VERSION 5.8 ;
BUSBITCHARS "[]" ;
DIVIDERCHAR "/" ;
UNITS
    DATABASE MICRONS 1000 ;
END UNITS

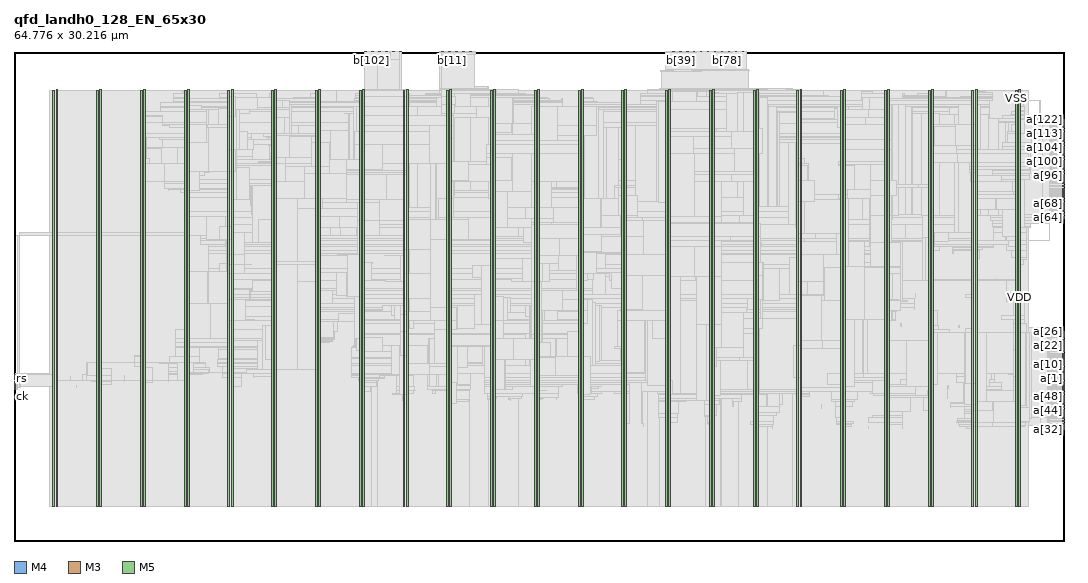
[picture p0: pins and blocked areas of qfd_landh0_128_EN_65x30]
MACRO qfd_landh0_128_EN_65x30
  FOREIGN qfd_landh0_128_EN_65x30 0 0 ;
  CLASS BLOCK ;
  SIZE 64.776 BY 30.216 ;
  PIN a[0]
    DIRECTION INPUT ;
    USE SIGNAL ;
    PORT
      LAYER M4 ;
        RECT  64.692 9.936 64.776 9.96 ;
    END
  END a[0]
  PIN a[100]
    DIRECTION INPUT ;
    USE SIGNAL ;
    PORT
      LAYER M4 ;
        RECT  64.692 23.376 64.776 23.4 ;
    END
  END a[100]
  PIN a[101]
    DIRECTION INPUT ;
    USE SIGNAL ;
    PORT
      LAYER M4 ;
        RECT  64.692 23.472 64.776 23.496 ;
    END
  END a[101]
  PIN a[102]
    DIRECTION INPUT ;
    USE SIGNAL ;
    PORT
      LAYER M4 ;
        RECT  64.692 23.568 64.776 23.592 ;
    END
  END a[102]
  PIN a[103]
    DIRECTION INPUT ;
    USE SIGNAL ;
    PORT
      LAYER M4 ;
        RECT  64.692 23.664 64.776 23.688 ;
    END
  END a[103]
  PIN a[104]
    DIRECTION INPUT ;
    USE SIGNAL ;
    PORT
      LAYER M4 ;
        RECT  64.692 23.76 64.776 23.784 ;
    END
  END a[104]
  PIN a[105]
    DIRECTION INPUT ;
    USE SIGNAL ;
    PORT
      LAYER M4 ;
        RECT  64.692 23.856 64.776 23.88 ;
    END
  END a[105]
  PIN a[106]
    DIRECTION INPUT ;
    USE SIGNAL ;
    PORT
      LAYER M4 ;
        RECT  64.692 23.952 64.776 23.976 ;
    END
  END a[106]
  PIN a[107]
    DIRECTION INPUT ;
    USE SIGNAL ;
    PORT
      LAYER M4 ;
        RECT  64.692 24.048 64.776 24.072 ;
    END
  END a[107]
  PIN a[108]
    DIRECTION INPUT ;
    USE SIGNAL ;
    PORT
      LAYER M4 ;
        RECT  64.692 24.144 64.776 24.168 ;
    END
  END a[108]
  PIN a[109]
    DIRECTION INPUT ;
    USE SIGNAL ;
    PORT
      LAYER M4 ;
        RECT  64.692 24.24 64.776 24.264 ;
    END
  END a[109]
  PIN a[10]
    DIRECTION INPUT ;
    USE SIGNAL ;
    PORT
      LAYER M4 ;
        RECT  64.692 10.896 64.776 10.92 ;
    END
  END a[10]
  PIN a[110]
    DIRECTION INPUT ;
    USE SIGNAL ;
    PORT
      LAYER M4 ;
        RECT  64.692 24.336 64.776 24.36 ;
    END
  END a[110]
  PIN a[111]
    DIRECTION INPUT ;
    USE SIGNAL ;
    PORT
      LAYER M4 ;
        RECT  64.692 24.432 64.776 24.456 ;
    END
  END a[111]
  PIN a[112]
    DIRECTION INPUT ;
    USE SIGNAL ;
    PORT
      LAYER M4 ;
        RECT  64.692 24.528 64.776 24.552 ;
    END
  END a[112]
  PIN a[113]
    DIRECTION INPUT ;
    USE SIGNAL ;
    PORT
      LAYER M4 ;
        RECT  64.692 24.624 64.776 24.648 ;
    END
  END a[113]
  PIN a[114]
    DIRECTION INPUT ;
    USE SIGNAL ;
    PORT
      LAYER M4 ;
        RECT  64.692 24.72 64.776 24.744 ;
    END
  END a[114]
  PIN a[115]
    DIRECTION INPUT ;
    USE SIGNAL ;
    PORT
      LAYER M4 ;
        RECT  64.692 24.816 64.776 24.84 ;
    END
  END a[115]
  PIN a[116]
    DIRECTION INPUT ;
    USE SIGNAL ;
    PORT
      LAYER M4 ;
        RECT  64.692 24.912 64.776 24.936 ;
    END
  END a[116]
  PIN a[117]
    DIRECTION INPUT ;
    USE SIGNAL ;
    PORT
      LAYER M4 ;
        RECT  64.692 25.008 64.776 25.032 ;
    END
  END a[117]
  PIN a[118]
    DIRECTION INPUT ;
    USE SIGNAL ;
    PORT
      LAYER M4 ;
        RECT  64.692 25.104 64.776 25.128 ;
    END
  END a[118]
  PIN a[119]
    DIRECTION INPUT ;
    USE SIGNAL ;
    PORT
      LAYER M4 ;
        RECT  64.692 25.2 64.776 25.224 ;
    END
  END a[119]
  PIN a[11]
    DIRECTION INPUT ;
    USE SIGNAL ;
    PORT
      LAYER M4 ;
        RECT  64.692 10.992 64.776 11.016 ;
    END
  END a[11]
  PIN a[120]
    DIRECTION INPUT ;
    USE SIGNAL ;
    PORT
      LAYER M4 ;
        RECT  64.692 25.296 64.776 25.32 ;
    END
  END a[120]
  PIN a[121]
    DIRECTION INPUT ;
    USE SIGNAL ;
    PORT
      LAYER M4 ;
        RECT  64.692 25.392 64.776 25.416 ;
    END
  END a[121]
  PIN a[122]
    DIRECTION INPUT ;
    USE SIGNAL ;
    PORT
      LAYER M4 ;
        RECT  64.692 25.488 64.776 25.512 ;
    END
  END a[122]
  PIN a[123]
    DIRECTION INPUT ;
    USE SIGNAL ;
    PORT
      LAYER M4 ;
        RECT  64.692 25.584 64.776 25.608 ;
    END
  END a[123]
  PIN a[124]
    DIRECTION INPUT ;
    USE SIGNAL ;
    PORT
      LAYER M4 ;
        RECT  64.692 25.68 64.776 25.704 ;
    END
  END a[124]
  PIN a[125]
    DIRECTION INPUT ;
    USE SIGNAL ;
    PORT
      LAYER M4 ;
        RECT  64.692 25.776 64.776 25.8 ;
    END
  END a[125]
  PIN a[126]
    DIRECTION INPUT ;
    USE SIGNAL ;
    PORT
      LAYER M4 ;
        RECT  64.692 25.872 64.776 25.896 ;
    END
  END a[126]
  PIN a[127]
    DIRECTION INPUT ;
    USE SIGNAL ;
    PORT
      LAYER M4 ;
        RECT  64.692 25.968 64.776 25.992 ;
    END
  END a[127]
  PIN a[12]
    DIRECTION INPUT ;
    USE SIGNAL ;
    PORT
      LAYER M4 ;
        RECT  64.692 11.088 64.776 11.112 ;
    END
  END a[12]
  PIN a[13]
    DIRECTION INPUT ;
    USE SIGNAL ;
    PORT
      LAYER M4 ;
        RECT  64.692 11.184 64.776 11.208 ;
    END
  END a[13]
  PIN a[14]
    DIRECTION INPUT ;
    USE SIGNAL ;
    PORT
      LAYER M4 ;
        RECT  64.692 11.28 64.776 11.304 ;
    END
  END a[14]
  PIN a[15]
    DIRECTION INPUT ;
    USE SIGNAL ;
    PORT
      LAYER M4 ;
        RECT  64.692 11.376 64.776 11.4 ;
    END
  END a[15]
  PIN a[16]
    DIRECTION INPUT ;
    USE SIGNAL ;
    PORT
      LAYER M4 ;
        RECT  64.692 11.472 64.776 11.496 ;
    END
  END a[16]
  PIN a[17]
    DIRECTION INPUT ;
    USE SIGNAL ;
    PORT
      LAYER M4 ;
        RECT  64.692 11.568 64.776 11.592 ;
    END
  END a[17]
  PIN a[18]
    DIRECTION INPUT ;
    USE SIGNAL ;
    PORT
      LAYER M4 ;
        RECT  64.692 11.664 64.776 11.688 ;
    END
  END a[18]
  PIN a[19]
    DIRECTION INPUT ;
    USE SIGNAL ;
    PORT
      LAYER M4 ;
        RECT  64.692 11.76 64.776 11.784 ;
    END
  END a[19]
  PIN a[1]
    DIRECTION INPUT ;
    USE SIGNAL ;
    PORT
      LAYER M4 ;
        RECT  64.692 10.032 64.776 10.056 ;
    END
  END a[1]
  PIN a[20]
    DIRECTION INPUT ;
    USE SIGNAL ;
    PORT
      LAYER M4 ;
        RECT  64.692 11.856 64.776 11.88 ;
    END
  END a[20]
  PIN a[21]
    DIRECTION INPUT ;
    USE SIGNAL ;
    PORT
      LAYER M4 ;
        RECT  64.692 11.952 64.776 11.976 ;
    END
  END a[21]
  PIN a[22]
    DIRECTION INPUT ;
    USE SIGNAL ;
    PORT
      LAYER M4 ;
        RECT  64.692 12.048 64.776 12.072 ;
    END
  END a[22]
  PIN a[23]
    DIRECTION INPUT ;
    USE SIGNAL ;
    PORT
      LAYER M4 ;
        RECT  64.692 12.144 64.776 12.168 ;
    END
  END a[23]
  PIN a[24]
    DIRECTION INPUT ;
    USE SIGNAL ;
    PORT
      LAYER M4 ;
        RECT  64.692 12.24 64.776 12.264 ;
    END
  END a[24]
  PIN a[25]
    DIRECTION INPUT ;
    USE SIGNAL ;
    PORT
      LAYER M4 ;
        RECT  64.692 12.336 64.776 12.36 ;
    END
  END a[25]
  PIN a[26]
    DIRECTION INPUT ;
    USE SIGNAL ;
    PORT
      LAYER M4 ;
        RECT  64.692 12.432 64.776 12.456 ;
    END
  END a[26]
  PIN a[27]
    DIRECTION INPUT ;
    USE SIGNAL ;
    PORT
      LAYER M4 ;
        RECT  64.692 12.528 64.776 12.552 ;
    END
  END a[27]
  PIN a[28]
    DIRECTION INPUT ;
    USE SIGNAL ;
    PORT
      LAYER M4 ;
        RECT  64.692 12.624 64.776 12.648 ;
    END
  END a[28]
  PIN a[29]
    DIRECTION INPUT ;
    USE SIGNAL ;
    PORT
      LAYER M4 ;
        RECT  64.692 12.72 64.776 12.744 ;
    END
  END a[29]
  PIN a[2]
    DIRECTION INPUT ;
    USE SIGNAL ;
    PORT
      LAYER M4 ;
        RECT  64.692 10.128 64.776 10.152 ;
    END
  END a[2]
  PIN a[30]
    DIRECTION INPUT ;
    USE SIGNAL ;
    PORT
      LAYER M4 ;
        RECT  64.692 12.816 64.776 12.84 ;
    END
  END a[30]
  PIN a[31]
    DIRECTION INPUT ;
    USE SIGNAL ;
    PORT
      LAYER M4 ;
        RECT  64.692 12.912 64.776 12.936 ;
    END
  END a[31]
  PIN a[32]
    DIRECTION INPUT ;
    USE SIGNAL ;
    PORT
      LAYER M4 ;
        RECT  64.692 6.864 64.776 6.888 ;
    END
  END a[32]
  PIN a[33]
    DIRECTION INPUT ;
    USE SIGNAL ;
    PORT
      LAYER M4 ;
        RECT  64.692 6.96 64.776 6.984 ;
    END
  END a[33]
  PIN a[34]
    DIRECTION INPUT ;
    USE SIGNAL ;
    PORT
      LAYER M4 ;
        RECT  64.692 7.056 64.776 7.08 ;
    END
  END a[34]
  PIN a[35]
    DIRECTION INPUT ;
    USE SIGNAL ;
    PORT
      LAYER M4 ;
        RECT  64.692 7.152 64.776 7.176 ;
    END
  END a[35]
  PIN a[36]
    DIRECTION INPUT ;
    USE SIGNAL ;
    PORT
      LAYER M4 ;
        RECT  64.692 7.248 64.776 7.272 ;
    END
  END a[36]
  PIN a[37]
    DIRECTION INPUT ;
    USE SIGNAL ;
    PORT
      LAYER M4 ;
        RECT  64.692 7.344 64.776 7.368 ;
    END
  END a[37]
  PIN a[38]
    DIRECTION INPUT ;
    USE SIGNAL ;
    PORT
      LAYER M4 ;
        RECT  64.692 7.44 64.776 7.464 ;
    END
  END a[38]
  PIN a[39]
    DIRECTION INPUT ;
    USE SIGNAL ;
    PORT
      LAYER M4 ;
        RECT  64.692 7.536 64.776 7.56 ;
    END
  END a[39]
  PIN a[3]
    DIRECTION INPUT ;
    USE SIGNAL ;
    PORT
      LAYER M4 ;
        RECT  64.692 10.224 64.776 10.248 ;
    END
  END a[3]
  PIN a[40]
    DIRECTION INPUT ;
    USE SIGNAL ;
    PORT
      LAYER M4 ;
        RECT  64.692 7.632 64.776 7.656 ;
    END
  END a[40]
  PIN a[41]
    DIRECTION INPUT ;
    USE SIGNAL ;
    PORT
      LAYER M4 ;
        RECT  64.692 7.728 64.776 7.752 ;
    END
  END a[41]
  PIN a[42]
    DIRECTION INPUT ;
    USE SIGNAL ;
    PORT
      LAYER M4 ;
        RECT  64.692 7.824 64.776 7.848 ;
    END
  END a[42]
  PIN a[43]
    DIRECTION INPUT ;
    USE SIGNAL ;
    PORT
      LAYER M4 ;
        RECT  64.692 7.92 64.776 7.944 ;
    END
  END a[43]
  PIN a[44]
    DIRECTION INPUT ;
    USE SIGNAL ;
    PORT
      LAYER M4 ;
        RECT  64.692 8.016 64.776 8.04 ;
    END
  END a[44]
  PIN a[45]
    DIRECTION INPUT ;
    USE SIGNAL ;
    PORT
      LAYER M4 ;
        RECT  64.692 8.112 64.776 8.136 ;
    END
  END a[45]
  PIN a[46]
    DIRECTION INPUT ;
    USE SIGNAL ;
    PORT
      LAYER M4 ;
        RECT  64.692 8.208 64.776 8.232 ;
    END
  END a[46]
  PIN a[47]
    DIRECTION INPUT ;
    USE SIGNAL ;
    PORT
      LAYER M4 ;
        RECT  64.692 8.304 64.776 8.328 ;
    END
  END a[47]
  PIN a[48]
    DIRECTION INPUT ;
    USE SIGNAL ;
    PORT
      LAYER M4 ;
        RECT  64.692 8.4 64.776 8.424 ;
    END
  END a[48]
  PIN a[49]
    DIRECTION INPUT ;
    USE SIGNAL ;
    PORT
      LAYER M4 ;
        RECT  64.692 8.496 64.776 8.52 ;
    END
  END a[49]
  PIN a[4]
    DIRECTION INPUT ;
    USE SIGNAL ;
    PORT
      LAYER M4 ;
        RECT  64.692 10.32 64.776 10.344 ;
    END
  END a[4]
  PIN a[50]
    DIRECTION INPUT ;
    USE SIGNAL ;
    PORT
      LAYER M4 ;
        RECT  64.692 8.592 64.776 8.616 ;
    END
  END a[50]
  PIN a[51]
    DIRECTION INPUT ;
    USE SIGNAL ;
    PORT
      LAYER M4 ;
        RECT  64.692 8.688 64.776 8.712 ;
    END
  END a[51]
  PIN a[52]
    DIRECTION INPUT ;
    USE SIGNAL ;
    PORT
      LAYER M4 ;
        RECT  64.692 8.784 64.776 8.808 ;
    END
  END a[52]
  PIN a[53]
    DIRECTION INPUT ;
    USE SIGNAL ;
    PORT
      LAYER M4 ;
        RECT  64.692 8.88 64.776 8.904 ;
    END
  END a[53]
  PIN a[54]
    DIRECTION INPUT ;
    USE SIGNAL ;
    PORT
      LAYER M4 ;
        RECT  64.692 8.976 64.776 9 ;
    END
  END a[54]
  PIN a[55]
    DIRECTION INPUT ;
    USE SIGNAL ;
    PORT
      LAYER M4 ;
        RECT  64.692 9.072 64.776 9.096 ;
    END
  END a[55]
  PIN a[56]
    DIRECTION INPUT ;
    USE SIGNAL ;
    PORT
      LAYER M4 ;
        RECT  64.692 9.168 64.776 9.192 ;
    END
  END a[56]
  PIN a[57]
    DIRECTION INPUT ;
    USE SIGNAL ;
    PORT
      LAYER M4 ;
        RECT  64.692 9.264 64.776 9.288 ;
    END
  END a[57]
  PIN a[58]
    DIRECTION INPUT ;
    USE SIGNAL ;
    PORT
      LAYER M4 ;
        RECT  64.692 9.36 64.776 9.384 ;
    END
  END a[58]
  PIN a[59]
    DIRECTION INPUT ;
    USE SIGNAL ;
    PORT
      LAYER M4 ;
        RECT  64.692 9.456 64.776 9.48 ;
    END
  END a[59]
  PIN a[5]
    DIRECTION INPUT ;
    USE SIGNAL ;
    PORT
      LAYER M4 ;
        RECT  64.692 10.416 64.776 10.44 ;
    END
  END a[5]
  PIN a[60]
    DIRECTION INPUT ;
    USE SIGNAL ;
    PORT
      LAYER M4 ;
        RECT  64.692 9.552 64.776 9.576 ;
    END
  END a[60]
  PIN a[61]
    DIRECTION INPUT ;
    USE SIGNAL ;
    PORT
      LAYER M4 ;
        RECT  64.692 9.648 64.776 9.672 ;
    END
  END a[61]
  PIN a[62]
    DIRECTION INPUT ;
    USE SIGNAL ;
    PORT
      LAYER M4 ;
        RECT  64.692 9.744 64.776 9.768 ;
    END
  END a[62]
  PIN a[63]
    DIRECTION INPUT ;
    USE SIGNAL ;
    PORT
      LAYER M4 ;
        RECT  64.692 9.84 64.776 9.864 ;
    END
  END a[63]
  PIN a[64]
    DIRECTION INPUT ;
    USE SIGNAL ;
    PORT
      LAYER M4 ;
        RECT  64.692 19.92 64.776 19.944 ;
    END
  END a[64]
  PIN a[65]
    DIRECTION INPUT ;
    USE SIGNAL ;
    PORT
      LAYER M4 ;
        RECT  64.692 20.016 64.776 20.04 ;
    END
  END a[65]
  PIN a[66]
    DIRECTION INPUT ;
    USE SIGNAL ;
    PORT
      LAYER M4 ;
        RECT  64.692 20.112 64.776 20.136 ;
    END
  END a[66]
  PIN a[67]
    DIRECTION INPUT ;
    USE SIGNAL ;
    PORT
      LAYER M4 ;
        RECT  64.692 20.208 64.776 20.232 ;
    END
  END a[67]
  PIN a[68]
    DIRECTION INPUT ;
    USE SIGNAL ;
    PORT
      LAYER M4 ;
        RECT  64.692 20.304 64.776 20.328 ;
    END
  END a[68]
  PIN a[69]
    DIRECTION INPUT ;
    USE SIGNAL ;
    PORT
      LAYER M4 ;
        RECT  64.692 20.4 64.776 20.424 ;
    END
  END a[69]
  PIN a[6]
    DIRECTION INPUT ;
    USE SIGNAL ;
    PORT
      LAYER M4 ;
        RECT  64.692 10.512 64.776 10.536 ;
    END
  END a[6]
  PIN a[70]
    DIRECTION INPUT ;
    USE SIGNAL ;
    PORT
      LAYER M4 ;
        RECT  64.692 20.496 64.776 20.52 ;
    END
  END a[70]
  PIN a[71]
    DIRECTION INPUT ;
    USE SIGNAL ;
    PORT
      LAYER M4 ;
        RECT  64.692 20.592 64.776 20.616 ;
    END
  END a[71]
  PIN a[72]
    DIRECTION INPUT ;
    USE SIGNAL ;
    PORT
      LAYER M4 ;
        RECT  64.692 20.688 64.776 20.712 ;
    END
  END a[72]
  PIN a[73]
    DIRECTION INPUT ;
    USE SIGNAL ;
    PORT
      LAYER M4 ;
        RECT  64.692 20.784 64.776 20.808 ;
    END
  END a[73]
  PIN a[74]
    DIRECTION INPUT ;
    USE SIGNAL ;
    PORT
      LAYER M4 ;
        RECT  64.692 20.88 64.776 20.904 ;
    END
  END a[74]
  PIN a[75]
    DIRECTION INPUT ;
    USE SIGNAL ;
    PORT
      LAYER M4 ;
        RECT  64.692 20.976 64.776 21 ;
    END
  END a[75]
  PIN a[76]
    DIRECTION INPUT ;
    USE SIGNAL ;
    PORT
      LAYER M4 ;
        RECT  64.692 21.072 64.776 21.096 ;
    END
  END a[76]
  PIN a[77]
    DIRECTION INPUT ;
    USE SIGNAL ;
    PORT
      LAYER M4 ;
        RECT  64.692 21.168 64.776 21.192 ;
    END
  END a[77]
  PIN a[78]
    DIRECTION INPUT ;
    USE SIGNAL ;
    PORT
      LAYER M4 ;
        RECT  64.692 21.264 64.776 21.288 ;
    END
  END a[78]
  PIN a[79]
    DIRECTION INPUT ;
    USE SIGNAL ;
    PORT
      LAYER M4 ;
        RECT  64.692 21.36 64.776 21.384 ;
    END
  END a[79]
  PIN a[7]
    DIRECTION INPUT ;
    USE SIGNAL ;
    PORT
      LAYER M4 ;
        RECT  64.692 10.608 64.776 10.632 ;
    END
  END a[7]
  PIN a[80]
    DIRECTION INPUT ;
    USE SIGNAL ;
    PORT
      LAYER M4 ;
        RECT  64.692 21.456 64.776 21.48 ;
    END
  END a[80]
  PIN a[81]
    DIRECTION INPUT ;
    USE SIGNAL ;
    PORT
      LAYER M4 ;
        RECT  64.692 21.552 64.776 21.576 ;
    END
  END a[81]
  PIN a[82]
    DIRECTION INPUT ;
    USE SIGNAL ;
    PORT
      LAYER M4 ;
        RECT  64.692 21.648 64.776 21.672 ;
    END
  END a[82]
  PIN a[83]
    DIRECTION INPUT ;
    USE SIGNAL ;
    PORT
      LAYER M4 ;
        RECT  64.692 21.744 64.776 21.768 ;
    END
  END a[83]
  PIN a[84]
    DIRECTION INPUT ;
    USE SIGNAL ;
    PORT
      LAYER M4 ;
        RECT  64.692 21.84 64.776 21.864 ;
    END
  END a[84]
  PIN a[85]
    DIRECTION INPUT ;
    USE SIGNAL ;
    PORT
      LAYER M4 ;
        RECT  64.692 21.936 64.776 21.96 ;
    END
  END a[85]
  PIN a[86]
    DIRECTION INPUT ;
    USE SIGNAL ;
    PORT
      LAYER M4 ;
        RECT  64.692 22.032 64.776 22.056 ;
    END
  END a[86]
  PIN a[87]
    DIRECTION INPUT ;
    USE SIGNAL ;
    PORT
      LAYER M4 ;
        RECT  64.692 22.128 64.776 22.152 ;
    END
  END a[87]
  PIN a[88]
    DIRECTION INPUT ;
    USE SIGNAL ;
    PORT
      LAYER M4 ;
        RECT  64.692 22.224 64.776 22.248 ;
    END
  END a[88]
  PIN a[89]
    DIRECTION INPUT ;
    USE SIGNAL ;
    PORT
      LAYER M4 ;
        RECT  64.692 22.32 64.776 22.344 ;
    END
  END a[89]
  PIN a[8]
    DIRECTION INPUT ;
    USE SIGNAL ;
    PORT
      LAYER M4 ;
        RECT  64.692 10.704 64.776 10.728 ;
    END
  END a[8]
  PIN a[90]
    DIRECTION INPUT ;
    USE SIGNAL ;
    PORT
      LAYER M4 ;
        RECT  64.692 22.416 64.776 22.44 ;
    END
  END a[90]
  PIN a[91]
    DIRECTION INPUT ;
    USE SIGNAL ;
    PORT
      LAYER M4 ;
        RECT  64.692 22.512 64.776 22.536 ;
    END
  END a[91]
  PIN a[92]
    DIRECTION INPUT ;
    USE SIGNAL ;
    PORT
      LAYER M4 ;
        RECT  64.692 22.608 64.776 22.632 ;
    END
  END a[92]
  PIN a[93]
    DIRECTION INPUT ;
    USE SIGNAL ;
    PORT
      LAYER M4 ;
        RECT  64.692 22.704 64.776 22.728 ;
    END
  END a[93]
  PIN a[94]
    DIRECTION INPUT ;
    USE SIGNAL ;
    PORT
      LAYER M4 ;
        RECT  64.692 22.8 64.776 22.824 ;
    END
  END a[94]
  PIN a[95]
    DIRECTION INPUT ;
    USE SIGNAL ;
    PORT
      LAYER M4 ;
        RECT  64.692 22.896 64.776 22.92 ;
    END
  END a[95]
  PIN a[96]
    DIRECTION INPUT ;
    USE SIGNAL ;
    PORT
      LAYER M4 ;
        RECT  64.692 22.992 64.776 23.016 ;
    END
  END a[96]
  PIN a[97]
    DIRECTION INPUT ;
    USE SIGNAL ;
    PORT
      LAYER M4 ;
        RECT  64.692 23.088 64.776 23.112 ;
    END
  END a[97]
  PIN a[98]
    DIRECTION INPUT ;
    USE SIGNAL ;
    PORT
      LAYER M4 ;
        RECT  64.692 23.184 64.776 23.208 ;
    END
  END a[98]
  PIN a[99]
    DIRECTION INPUT ;
    USE SIGNAL ;
    PORT
      LAYER M4 ;
        RECT  64.692 23.28 64.776 23.304 ;
    END
  END a[99]
  PIN a[9]
    DIRECTION INPUT ;
    USE SIGNAL ;
    PORT
      LAYER M4 ;
        RECT  64.692 10.8 64.776 10.824 ;
    END
  END a[9]
  PIN b[0]
    DIRECTION OUTPUT ;
    USE SIGNAL ;
    PORT
      LAYER M3 ;
        RECT  26.244 30.179 26.262 30.216 ;
    END
  END b[0]
  PIN b[100]
    DIRECTION OUTPUT ;
    USE SIGNAL ;
    PORT
      LAYER M3 ;
        RECT  21.924 30.179 21.942 30.216 ;
    END
  END b[100]
  PIN b[101]
    DIRECTION OUTPUT ;
    USE SIGNAL ;
    PORT
      LAYER M3 ;
        RECT  21.996 30.179 22.014 30.216 ;
    END
  END b[101]
  PIN b[102]
    DIRECTION OUTPUT ;
    USE SIGNAL ;
    PORT
      LAYER M3 ;
        RECT  22.068 30.179 22.086 30.216 ;
    END
  END b[102]
  PIN b[103]
    DIRECTION OUTPUT ;
    USE SIGNAL ;
    PORT
      LAYER M3 ;
        RECT  22.14 30.179 22.158 30.216 ;
    END
  END b[103]
  PIN b[104]
    DIRECTION OUTPUT ;
    USE SIGNAL ;
    PORT
      LAYER M3 ;
        RECT  22.212 30.179 22.23 30.216 ;
    END
  END b[104]
  PIN b[105]
    DIRECTION OUTPUT ;
    USE SIGNAL ;
    PORT
      LAYER M3 ;
        RECT  22.284 30.179 22.302 30.216 ;
    END
  END b[105]
  PIN b[106]
    DIRECTION OUTPUT ;
    USE SIGNAL ;
    PORT
      LAYER M3 ;
        RECT  22.356 30.179 22.374 30.216 ;
    END
  END b[106]
  PIN b[107]
    DIRECTION OUTPUT ;
    USE SIGNAL ;
    PORT
      LAYER M3 ;
        RECT  22.428 30.179 22.446 30.216 ;
    END
  END b[107]
  PIN b[108]
    DIRECTION OUTPUT ;
    USE SIGNAL ;
    PORT
      LAYER M3 ;
        RECT  22.5 30.179 22.518 30.216 ;
    END
  END b[108]
  PIN b[109]
    DIRECTION OUTPUT ;
    USE SIGNAL ;
    PORT
      LAYER M3 ;
        RECT  22.572 30.179 22.59 30.216 ;
    END
  END b[109]
  PIN b[10]
    DIRECTION OUTPUT ;
    USE SIGNAL ;
    PORT
      LAYER M3 ;
        RECT  26.964 30.179 26.982 30.216 ;
    END
  END b[10]
  PIN b[110]
    DIRECTION OUTPUT ;
    USE SIGNAL ;
    PORT
      LAYER M3 ;
        RECT  22.644 30.179 22.662 30.216 ;
    END
  END b[110]
  PIN b[111]
    DIRECTION OUTPUT ;
    USE SIGNAL ;
    PORT
      LAYER M3 ;
        RECT  22.716 30.179 22.734 30.216 ;
    END
  END b[111]
  PIN b[112]
    DIRECTION OUTPUT ;
    USE SIGNAL ;
    PORT
      LAYER M3 ;
        RECT  22.788 30.179 22.806 30.216 ;
    END
  END b[112]
  PIN b[113]
    DIRECTION OUTPUT ;
    USE SIGNAL ;
    PORT
      LAYER M3 ;
        RECT  22.86 30.179 22.878 30.216 ;
    END
  END b[113]
  PIN b[114]
    DIRECTION OUTPUT ;
    USE SIGNAL ;
    PORT
      LAYER M3 ;
        RECT  22.932 30.179 22.95 30.216 ;
    END
  END b[114]
  PIN b[115]
    DIRECTION OUTPUT ;
    USE SIGNAL ;
    PORT
      LAYER M3 ;
        RECT  23.004 30.179 23.022 30.216 ;
    END
  END b[115]
  PIN b[116]
    DIRECTION OUTPUT ;
    USE SIGNAL ;
    PORT
      LAYER M3 ;
        RECT  23.076 30.179 23.094 30.216 ;
    END
  END b[116]
  PIN b[117]
    DIRECTION OUTPUT ;
    USE SIGNAL ;
    PORT
      LAYER M3 ;
        RECT  23.148 30.179 23.166 30.216 ;
    END
  END b[117]
  PIN b[118]
    DIRECTION OUTPUT ;
    USE SIGNAL ;
    PORT
      LAYER M3 ;
        RECT  23.22 30.179 23.238 30.216 ;
    END
  END b[118]
  PIN b[119]
    DIRECTION OUTPUT ;
    USE SIGNAL ;
    PORT
      LAYER M3 ;
        RECT  23.292 30.179 23.31 30.216 ;
    END
  END b[119]
  PIN b[11]
    DIRECTION OUTPUT ;
    USE SIGNAL ;
    PORT
      LAYER M3 ;
        RECT  27.036 30.179 27.054 30.216 ;
    END
  END b[11]
  PIN b[120]
    DIRECTION OUTPUT ;
    USE SIGNAL ;
    PORT
      LAYER M3 ;
        RECT  23.364 30.179 23.382 30.216 ;
    END
  END b[120]
  PIN b[121]
    DIRECTION OUTPUT ;
    USE SIGNAL ;
    PORT
      LAYER M3 ;
        RECT  23.436 30.179 23.454 30.216 ;
    END
  END b[121]
  PIN b[122]
    DIRECTION OUTPUT ;
    USE SIGNAL ;
    PORT
      LAYER M3 ;
        RECT  23.508 30.179 23.526 30.216 ;
    END
  END b[122]
  PIN b[123]
    DIRECTION OUTPUT ;
    USE SIGNAL ;
    PORT
      LAYER M3 ;
        RECT  23.58 30.179 23.598 30.216 ;
    END
  END b[123]
  PIN b[124]
    DIRECTION OUTPUT ;
    USE SIGNAL ;
    PORT
      LAYER M3 ;
        RECT  23.652 30.179 23.67 30.216 ;
    END
  END b[124]
  PIN b[125]
    DIRECTION OUTPUT ;
    USE SIGNAL ;
    PORT
      LAYER M3 ;
        RECT  23.724 30.179 23.742 30.216 ;
    END
  END b[125]
  PIN b[126]
    DIRECTION OUTPUT ;
    USE SIGNAL ;
    PORT
      LAYER M3 ;
        RECT  23.796 30.179 23.814 30.216 ;
    END
  END b[126]
  PIN b[127]
    DIRECTION OUTPUT ;
    USE SIGNAL ;
    PORT
      LAYER M3 ;
        RECT  23.868 30.179 23.886 30.216 ;
    END
  END b[127]
  PIN b[12]
    DIRECTION OUTPUT ;
    USE SIGNAL ;
    PORT
      LAYER M3 ;
        RECT  27.108 30.179 27.126 30.216 ;
    END
  END b[12]
  PIN b[13]
    DIRECTION OUTPUT ;
    USE SIGNAL ;
    PORT
      LAYER M3 ;
        RECT  27.18 30.179 27.198 30.216 ;
    END
  END b[13]
  PIN b[14]
    DIRECTION OUTPUT ;
    USE SIGNAL ;
    PORT
      LAYER M3 ;
        RECT  27.252 30.179 27.27 30.216 ;
    END
  END b[14]
  PIN b[15]
    DIRECTION OUTPUT ;
    USE SIGNAL ;
    PORT
      LAYER M3 ;
        RECT  27.324 30.179 27.342 30.216 ;
    END
  END b[15]
  PIN b[16]
    DIRECTION OUTPUT ;
    USE SIGNAL ;
    PORT
      LAYER M3 ;
        RECT  27.396 30.179 27.414 30.216 ;
    END
  END b[16]
  PIN b[17]
    DIRECTION OUTPUT ;
    USE SIGNAL ;
    PORT
      LAYER M3 ;
        RECT  27.468 30.179 27.486 30.216 ;
    END
  END b[17]
  PIN b[18]
    DIRECTION OUTPUT ;
    USE SIGNAL ;
    PORT
      LAYER M3 ;
        RECT  27.54 30.179 27.558 30.216 ;
    END
  END b[18]
  PIN b[19]
    DIRECTION OUTPUT ;
    USE SIGNAL ;
    PORT
      LAYER M3 ;
        RECT  27.612 30.179 27.63 30.216 ;
    END
  END b[19]
  PIN b[1]
    DIRECTION OUTPUT ;
    USE SIGNAL ;
    PORT
      LAYER M3 ;
        RECT  26.316 30.179 26.334 30.216 ;
    END
  END b[1]
  PIN b[20]
    DIRECTION OUTPUT ;
    USE SIGNAL ;
    PORT
      LAYER M3 ;
        RECT  27.684 30.179 27.702 30.216 ;
    END
  END b[20]
  PIN b[21]
    DIRECTION OUTPUT ;
    USE SIGNAL ;
    PORT
      LAYER M3 ;
        RECT  27.756 30.179 27.774 30.216 ;
    END
  END b[21]
  PIN b[22]
    DIRECTION OUTPUT ;
    USE SIGNAL ;
    PORT
      LAYER M3 ;
        RECT  27.828 30.179 27.846 30.216 ;
    END
  END b[22]
  PIN b[23]
    DIRECTION OUTPUT ;
    USE SIGNAL ;
    PORT
      LAYER M3 ;
        RECT  27.9 30.179 27.918 30.216 ;
    END
  END b[23]
  PIN b[24]
    DIRECTION OUTPUT ;
    USE SIGNAL ;
    PORT
      LAYER M3 ;
        RECT  27.972 30.179 27.99 30.216 ;
    END
  END b[24]
  PIN b[25]
    DIRECTION OUTPUT ;
    USE SIGNAL ;
    PORT
      LAYER M3 ;
        RECT  28.044 30.179 28.062 30.216 ;
    END
  END b[25]
  PIN b[26]
    DIRECTION OUTPUT ;
    USE SIGNAL ;
    PORT
      LAYER M3 ;
        RECT  28.116 30.179 28.134 30.216 ;
    END
  END b[26]
  PIN b[27]
    DIRECTION OUTPUT ;
    USE SIGNAL ;
    PORT
      LAYER M3 ;
        RECT  28.188 30.179 28.206 30.216 ;
    END
  END b[27]
  PIN b[28]
    DIRECTION OUTPUT ;
    USE SIGNAL ;
    PORT
      LAYER M3 ;
        RECT  28.26 30.179 28.278 30.216 ;
    END
  END b[28]
  PIN b[29]
    DIRECTION OUTPUT ;
    USE SIGNAL ;
    PORT
      LAYER M3 ;
        RECT  28.332 30.179 28.35 30.216 ;
    END
  END b[29]
  PIN b[2]
    DIRECTION OUTPUT ;
    USE SIGNAL ;
    PORT
      LAYER M3 ;
        RECT  26.388 30.179 26.406 30.216 ;
    END
  END b[2]
  PIN b[30]
    DIRECTION OUTPUT ;
    USE SIGNAL ;
    PORT
      LAYER M3 ;
        RECT  28.404 30.179 28.422 30.216 ;
    END
  END b[30]
  PIN b[31]
    DIRECTION OUTPUT ;
    USE SIGNAL ;
    PORT
      LAYER M3 ;
        RECT  28.476 30.179 28.494 30.216 ;
    END
  END b[31]
  PIN b[32]
    DIRECTION OUTPUT ;
    USE SIGNAL ;
    PORT
      LAYER M3 ;
        RECT  40.644 30.179 40.662 30.216 ;
    END
  END b[32]
  PIN b[33]
    DIRECTION OUTPUT ;
    USE SIGNAL ;
    PORT
      LAYER M3 ;
        RECT  40.716 30.179 40.734 30.216 ;
    END
  END b[33]
  PIN b[34]
    DIRECTION OUTPUT ;
    USE SIGNAL ;
    PORT
      LAYER M3 ;
        RECT  40.788 30.179 40.806 30.216 ;
    END
  END b[34]
  PIN b[35]
    DIRECTION OUTPUT ;
    USE SIGNAL ;
    PORT
      LAYER M3 ;
        RECT  40.86 30.179 40.878 30.216 ;
    END
  END b[35]
  PIN b[36]
    DIRECTION OUTPUT ;
    USE SIGNAL ;
    PORT
      LAYER M3 ;
        RECT  40.932 30.179 40.95 30.216 ;
    END
  END b[36]
  PIN b[37]
    DIRECTION OUTPUT ;
    USE SIGNAL ;
    PORT
      LAYER M3 ;
        RECT  41.004 30.179 41.022 30.216 ;
    END
  END b[37]
  PIN b[38]
    DIRECTION OUTPUT ;
    USE SIGNAL ;
    PORT
      LAYER M3 ;
        RECT  41.076 30.179 41.094 30.216 ;
    END
  END b[38]
  PIN b[39]
    DIRECTION OUTPUT ;
    USE SIGNAL ;
    PORT
      LAYER M3 ;
        RECT  41.148 30.179 41.166 30.216 ;
    END
  END b[39]
  PIN b[3]
    DIRECTION OUTPUT ;
    USE SIGNAL ;
    PORT
      LAYER M3 ;
        RECT  26.46 30.179 26.478 30.216 ;
    END
  END b[3]
  PIN b[40]
    DIRECTION OUTPUT ;
    USE SIGNAL ;
    PORT
      LAYER M3 ;
        RECT  41.22 30.179 41.238 30.216 ;
    END
  END b[40]
  PIN b[41]
    DIRECTION OUTPUT ;
    USE SIGNAL ;
    PORT
      LAYER M3 ;
        RECT  41.292 30.179 41.31 30.216 ;
    END
  END b[41]
  PIN b[42]
    DIRECTION OUTPUT ;
    USE SIGNAL ;
    PORT
      LAYER M3 ;
        RECT  41.364 30.179 41.382 30.216 ;
    END
  END b[42]
  PIN b[43]
    DIRECTION OUTPUT ;
    USE SIGNAL ;
    PORT
      LAYER M3 ;
        RECT  41.436 30.179 41.454 30.216 ;
    END
  END b[43]
  PIN b[44]
    DIRECTION OUTPUT ;
    USE SIGNAL ;
    PORT
      LAYER M3 ;
        RECT  41.508 30.179 41.526 30.216 ;
    END
  END b[44]
  PIN b[45]
    DIRECTION OUTPUT ;
    USE SIGNAL ;
    PORT
      LAYER M3 ;
        RECT  41.58 30.179 41.598 30.216 ;
    END
  END b[45]
  PIN b[46]
    DIRECTION OUTPUT ;
    USE SIGNAL ;
    PORT
      LAYER M3 ;
        RECT  41.652 30.179 41.67 30.216 ;
    END
  END b[46]
  PIN b[47]
    DIRECTION OUTPUT ;
    USE SIGNAL ;
    PORT
      LAYER M3 ;
        RECT  41.724 30.179 41.742 30.216 ;
    END
  END b[47]
  PIN b[48]
    DIRECTION OUTPUT ;
    USE SIGNAL ;
    PORT
      LAYER M3 ;
        RECT  41.796 30.179 41.814 30.216 ;
    END
  END b[48]
  PIN b[49]
    DIRECTION OUTPUT ;
    USE SIGNAL ;
    PORT
      LAYER M3 ;
        RECT  41.868 30.179 41.886 30.216 ;
    END
  END b[49]
  PIN b[4]
    DIRECTION OUTPUT ;
    USE SIGNAL ;
    PORT
      LAYER M3 ;
        RECT  26.532 30.179 26.55 30.216 ;
    END
  END b[4]
  PIN b[50]
    DIRECTION OUTPUT ;
    USE SIGNAL ;
    PORT
      LAYER M3 ;
        RECT  41.94 30.179 41.958 30.216 ;
    END
  END b[50]
  PIN b[51]
    DIRECTION OUTPUT ;
    USE SIGNAL ;
    PORT
      LAYER M3 ;
        RECT  42.012 30.179 42.03 30.216 ;
    END
  END b[51]
  PIN b[52]
    DIRECTION OUTPUT ;
    USE SIGNAL ;
    PORT
      LAYER M3 ;
        RECT  42.084 30.179 42.102 30.216 ;
    END
  END b[52]
  PIN b[53]
    DIRECTION OUTPUT ;
    USE SIGNAL ;
    PORT
      LAYER M3 ;
        RECT  42.156 30.179 42.174 30.216 ;
    END
  END b[53]
  PIN b[54]
    DIRECTION OUTPUT ;
    USE SIGNAL ;
    PORT
      LAYER M3 ;
        RECT  42.228 30.179 42.246 30.216 ;
    END
  END b[54]
  PIN b[55]
    DIRECTION OUTPUT ;
    USE SIGNAL ;
    PORT
      LAYER M3 ;
        RECT  42.3 30.179 42.318 30.216 ;
    END
  END b[55]
  PIN b[56]
    DIRECTION OUTPUT ;
    USE SIGNAL ;
    PORT
      LAYER M3 ;
        RECT  42.372 30.179 42.39 30.216 ;
    END
  END b[56]
  PIN b[57]
    DIRECTION OUTPUT ;
    USE SIGNAL ;
    PORT
      LAYER M3 ;
        RECT  42.444 30.179 42.462 30.216 ;
    END
  END b[57]
  PIN b[58]
    DIRECTION OUTPUT ;
    USE SIGNAL ;
    PORT
      LAYER M3 ;
        RECT  42.516 30.179 42.534 30.216 ;
    END
  END b[58]
  PIN b[59]
    DIRECTION OUTPUT ;
    USE SIGNAL ;
    PORT
      LAYER M3 ;
        RECT  42.588 30.179 42.606 30.216 ;
    END
  END b[59]
  PIN b[5]
    DIRECTION OUTPUT ;
    USE SIGNAL ;
    PORT
      LAYER M3 ;
        RECT  26.604 30.179 26.622 30.216 ;
    END
  END b[5]
  PIN b[60]
    DIRECTION OUTPUT ;
    USE SIGNAL ;
    PORT
      LAYER M3 ;
        RECT  42.66 30.179 42.678 30.216 ;
    END
  END b[60]
  PIN b[61]
    DIRECTION OUTPUT ;
    USE SIGNAL ;
    PORT
      LAYER M3 ;
        RECT  42.732 30.179 42.75 30.216 ;
    END
  END b[61]
  PIN b[62]
    DIRECTION OUTPUT ;
    USE SIGNAL ;
    PORT
      LAYER M3 ;
        RECT  42.804 30.179 42.822 30.216 ;
    END
  END b[62]
  PIN b[63]
    DIRECTION OUTPUT ;
    USE SIGNAL ;
    PORT
      LAYER M3 ;
        RECT  42.876 30.179 42.894 30.216 ;
    END
  END b[63]
  PIN b[64]
    DIRECTION OUTPUT ;
    USE SIGNAL ;
    PORT
      LAYER M3 ;
        RECT  42.948 30.179 42.966 30.216 ;
    END
  END b[64]
  PIN b[65]
    DIRECTION OUTPUT ;
    USE SIGNAL ;
    PORT
      LAYER M3 ;
        RECT  43.02 30.179 43.038 30.216 ;
    END
  END b[65]
  PIN b[66]
    DIRECTION OUTPUT ;
    USE SIGNAL ;
    PORT
      LAYER M3 ;
        RECT  43.092 30.179 43.11 30.216 ;
    END
  END b[66]
  PIN b[67]
    DIRECTION OUTPUT ;
    USE SIGNAL ;
    PORT
      LAYER M3 ;
        RECT  43.164 30.179 43.182 30.216 ;
    END
  END b[67]
  PIN b[68]
    DIRECTION OUTPUT ;
    USE SIGNAL ;
    PORT
      LAYER M3 ;
        RECT  43.236 30.179 43.254 30.216 ;
    END
  END b[68]
  PIN b[69]
    DIRECTION OUTPUT ;
    USE SIGNAL ;
    PORT
      LAYER M3 ;
        RECT  43.308 30.179 43.326 30.216 ;
    END
  END b[69]
  PIN b[6]
    DIRECTION OUTPUT ;
    USE SIGNAL ;
    PORT
      LAYER M3 ;
        RECT  26.676 30.179 26.694 30.216 ;
    END
  END b[6]
  PIN b[70]
    DIRECTION OUTPUT ;
    USE SIGNAL ;
    PORT
      LAYER M3 ;
        RECT  43.38 30.179 43.398 30.216 ;
    END
  END b[70]
  PIN b[71]
    DIRECTION OUTPUT ;
    USE SIGNAL ;
    PORT
      LAYER M3 ;
        RECT  43.452 30.179 43.47 30.216 ;
    END
  END b[71]
  PIN b[72]
    DIRECTION OUTPUT ;
    USE SIGNAL ;
    PORT
      LAYER M3 ;
        RECT  43.524 30.179 43.542 30.216 ;
    END
  END b[72]
  PIN b[73]
    DIRECTION OUTPUT ;
    USE SIGNAL ;
    PORT
      LAYER M3 ;
        RECT  43.596 30.179 43.614 30.216 ;
    END
  END b[73]
  PIN b[74]
    DIRECTION OUTPUT ;
    USE SIGNAL ;
    PORT
      LAYER M3 ;
        RECT  43.668 30.179 43.686 30.216 ;
    END
  END b[74]
  PIN b[75]
    DIRECTION OUTPUT ;
    USE SIGNAL ;
    PORT
      LAYER M3 ;
        RECT  43.74 30.179 43.758 30.216 ;
    END
  END b[75]
  PIN b[76]
    DIRECTION OUTPUT ;
    USE SIGNAL ;
    PORT
      LAYER M3 ;
        RECT  43.812 30.179 43.83 30.216 ;
    END
  END b[76]
  PIN b[77]
    DIRECTION OUTPUT ;
    USE SIGNAL ;
    PORT
      LAYER M3 ;
        RECT  43.884 30.179 43.902 30.216 ;
    END
  END b[77]
  PIN b[78]
    DIRECTION OUTPUT ;
    USE SIGNAL ;
    PORT
      LAYER M3 ;
        RECT  43.956 30.179 43.974 30.216 ;
    END
  END b[78]
  PIN b[79]
    DIRECTION OUTPUT ;
    USE SIGNAL ;
    PORT
      LAYER M3 ;
        RECT  44.028 30.179 44.046 30.216 ;
    END
  END b[79]
  PIN b[7]
    DIRECTION OUTPUT ;
    USE SIGNAL ;
    PORT
      LAYER M3 ;
        RECT  26.748 30.179 26.766 30.216 ;
    END
  END b[7]
  PIN b[80]
    DIRECTION OUTPUT ;
    USE SIGNAL ;
    PORT
      LAYER M3 ;
        RECT  44.1 30.179 44.118 30.216 ;
    END
  END b[80]
  PIN b[81]
    DIRECTION OUTPUT ;
    USE SIGNAL ;
    PORT
      LAYER M3 ;
        RECT  44.172 30.179 44.19 30.216 ;
    END
  END b[81]
  PIN b[82]
    DIRECTION OUTPUT ;
    USE SIGNAL ;
    PORT
      LAYER M3 ;
        RECT  44.244 30.179 44.262 30.216 ;
    END
  END b[82]
  PIN b[83]
    DIRECTION OUTPUT ;
    USE SIGNAL ;
    PORT
      LAYER M3 ;
        RECT  44.316 30.179 44.334 30.216 ;
    END
  END b[83]
  PIN b[84]
    DIRECTION OUTPUT ;
    USE SIGNAL ;
    PORT
      LAYER M3 ;
        RECT  44.388 30.179 44.406 30.216 ;
    END
  END b[84]
  PIN b[85]
    DIRECTION OUTPUT ;
    USE SIGNAL ;
    PORT
      LAYER M3 ;
        RECT  44.46 30.179 44.478 30.216 ;
    END
  END b[85]
  PIN b[86]
    DIRECTION OUTPUT ;
    USE SIGNAL ;
    PORT
      LAYER M3 ;
        RECT  44.532 30.179 44.55 30.216 ;
    END
  END b[86]
  PIN b[87]
    DIRECTION OUTPUT ;
    USE SIGNAL ;
    PORT
      LAYER M3 ;
        RECT  44.604 30.179 44.622 30.216 ;
    END
  END b[87]
  PIN b[88]
    DIRECTION OUTPUT ;
    USE SIGNAL ;
    PORT
      LAYER M3 ;
        RECT  44.676 30.179 44.694 30.216 ;
    END
  END b[88]
  PIN b[89]
    DIRECTION OUTPUT ;
    USE SIGNAL ;
    PORT
      LAYER M3 ;
        RECT  44.748 30.179 44.766 30.216 ;
    END
  END b[89]
  PIN b[8]
    DIRECTION OUTPUT ;
    USE SIGNAL ;
    PORT
      LAYER M3 ;
        RECT  26.82 30.179 26.838 30.216 ;
    END
  END b[8]
  PIN b[90]
    DIRECTION OUTPUT ;
    USE SIGNAL ;
    PORT
      LAYER M3 ;
        RECT  44.82 30.179 44.838 30.216 ;
    END
  END b[90]
  PIN b[91]
    DIRECTION OUTPUT ;
    USE SIGNAL ;
    PORT
      LAYER M3 ;
        RECT  44.892 30.179 44.91 30.216 ;
    END
  END b[91]
  PIN b[92]
    DIRECTION OUTPUT ;
    USE SIGNAL ;
    PORT
      LAYER M3 ;
        RECT  44.964 30.179 44.982 30.216 ;
    END
  END b[92]
  PIN b[93]
    DIRECTION OUTPUT ;
    USE SIGNAL ;
    PORT
      LAYER M3 ;
        RECT  45.036 30.179 45.054 30.216 ;
    END
  END b[93]
  PIN b[94]
    DIRECTION OUTPUT ;
    USE SIGNAL ;
    PORT
      LAYER M3 ;
        RECT  45.108 30.179 45.126 30.216 ;
    END
  END b[94]
  PIN b[95]
    DIRECTION OUTPUT ;
    USE SIGNAL ;
    PORT
      LAYER M3 ;
        RECT  45.18 30.179 45.198 30.216 ;
    END
  END b[95]
  PIN b[96]
    DIRECTION OUTPUT ;
    USE SIGNAL ;
    PORT
      LAYER M3 ;
        RECT  21.636 30.179 21.654 30.216 ;
    END
  END b[96]
  PIN b[97]
    DIRECTION OUTPUT ;
    USE SIGNAL ;
    PORT
      LAYER M3 ;
        RECT  21.708 30.179 21.726 30.216 ;
    END
  END b[97]
  PIN b[98]
    DIRECTION OUTPUT ;
    USE SIGNAL ;
    PORT
      LAYER M3 ;
        RECT  21.78 30.179 21.798 30.216 ;
    END
  END b[98]
  PIN b[99]
    DIRECTION OUTPUT ;
    USE SIGNAL ;
    PORT
      LAYER M3 ;
        RECT  21.852 30.179 21.87 30.216 ;
    END
  END b[99]
  PIN b[9]
    DIRECTION OUTPUT ;
    USE SIGNAL ;
    PORT
      LAYER M3 ;
        RECT  26.892 30.179 26.91 30.216 ;
    END
  END b[9]
  PIN ck
    DIRECTION INPUT ;
    USE SIGNAL ;
    PORT
      LAYER M4 ;
        RECT  0 9.36 0.084 9.384 ;
    END
  END ck
  PIN ck_s
    DIRECTION INPUT ;
    USE SIGNAL ;
    PORT
      LAYER M4 ;
        RECT  0 9.456 0.084 9.48 ;
    END
  END ck_s
  PIN en
    DIRECTION INPUT ;
    USE SIGNAL ;
    PORT
      LAYER M4 ;
        RECT  0 9.552 0.084 9.576 ;
    END
  END en
  PIN fault
    DIRECTION OUTPUT ;
    USE SIGNAL ;
    PORT
      LAYER M4 ;
        RECT  0 9.648 0.084 9.672 ;
    END
  END fault
  PIN k0
    DIRECTION INPUT ;
    USE SIGNAL ;
    PORT
      LAYER M4 ;
        RECT  0 9.744 0.084 9.768 ;
    END
  END k0
  PIN k1
    DIRECTION INPUT ;
    USE SIGNAL ;
    PORT
      LAYER M4 ;
        RECT  0 9.84 0.084 9.864 ;
    END
  END k1
  PIN k2
    DIRECTION INPUT ;
    USE SIGNAL ;
    PORT
      LAYER M4 ;
        RECT  0 9.936 0.084 9.96 ;
    END
  END k2
  PIN rs
    DIRECTION INPUT ;
    USE SIGNAL ;
    PORT
      LAYER M4 ;
        RECT  0 10.032 0.084 10.056 ;
    END
  END rs
  PIN tie_hi
    DIRECTION OUTPUT ;
    USE SIGNAL ;
    PORT
      LAYER M4 ;
        RECT  0 10.128 0.084 10.152 ;
    END
  END tie_hi
  PIN tie_lo
    DIRECTION OUTPUT ;
    USE SIGNAL ;
    PORT
      LAYER M4 ;
        RECT  0 10.224 0.084 10.248 ;
    END
  END tie_lo
  PIN VDD
    DIRECTION INOUT ;
    USE POWER ;
    PORT
      LAYER M5 ;
        RECT  61.992 2.151 62.112 27.833 ;
        RECT  59.292 2.151 59.412 27.833 ;
        RECT  56.592 2.151 56.712 27.833 ;
        RECT  53.892 2.151 54.012 27.833 ;
        RECT  51.192 2.151 51.312 27.833 ;
        RECT  48.492 2.151 48.612 27.833 ;
        RECT  45.792 2.151 45.912 27.833 ;
        RECT  43.092 2.151 43.212 27.833 ;
        RECT  40.392 2.151 40.512 27.833 ;
        RECT  37.692 2.151 37.812 27.833 ;
        RECT  34.992 2.151 35.112 27.833 ;
        RECT  32.292 2.151 32.412 27.833 ;
        RECT  29.592 2.151 29.712 27.833 ;
        RECT  26.892 2.151 27.012 27.833 ;
        RECT  24.192 2.151 24.312 27.833 ;
        RECT  21.492 2.151 21.612 27.833 ;
        RECT  18.792 2.151 18.912 27.833 ;
        RECT  16.092 2.151 16.212 27.833 ;
        RECT  13.392 2.151 13.512 27.833 ;
        RECT  10.692 2.151 10.812 27.833 ;
        RECT  7.992 2.151 8.112 27.833 ;
        RECT  5.292 2.151 5.412 27.833 ;
        RECT  2.592 2.151 2.712 27.833 ;
    END
  END VDD
  PIN VSS
    DIRECTION INOUT ;
    USE GROUND ;
    PORT
      LAYER M5 ;
        RECT  61.8 2.137 61.92 27.819 ;
        RECT  59.1 2.137 59.22 27.819 ;
        RECT  56.4 2.137 56.52 27.819 ;
        RECT  53.7 2.137 53.82 27.819 ;
        RECT  51 2.137 51.12 27.819 ;
        RECT  48.3 2.137 48.42 27.819 ;
        RECT  45.6 2.137 45.72 27.819 ;
        RECT  42.9 2.137 43.02 27.819 ;
        RECT  40.2 2.137 40.32 27.819 ;
        RECT  37.5 2.137 37.62 27.819 ;
        RECT  34.8 2.137 34.92 27.819 ;
        RECT  32.1 2.137 32.22 27.819 ;
        RECT  29.4 2.137 29.52 27.819 ;
        RECT  26.7 2.137 26.82 27.819 ;
        RECT  24 2.137 24.12 27.819 ;
        RECT  21.3 2.137 21.42 27.819 ;
        RECT  18.6 2.137 18.72 27.819 ;
        RECT  15.9 2.137 16.02 27.819 ;
        RECT  13.2 2.137 13.32 27.819 ;
        RECT  10.5 2.137 10.62 27.819 ;
        RECT  7.8 2.137 7.92 27.819 ;
        RECT  5.1 2.137 5.22 27.819 ;
        RECT  2.4 2.137 2.52 27.819 ;
    END
  END VSS
  # OT_OBS_CLOSED layer=M5 d_um=1.536 added=135
  OBS
    LAYER RVTN ;
     RECT  2.16 2.16 62.586 2.295 ;
     RECT  2.16 2.565 62.586 2.835 ;
     RECT  2.16 3.105 62.586 3.375 ;
     RECT  2.16 3.645 62.586 3.915 ;
     RECT  2.16 4.185 62.586 4.455 ;
     RECT  2.16 4.725 62.586 4.995 ;
     RECT  2.16 5.265 62.586 5.535 ;
     RECT  2.16 5.805 62.586 6.075 ;
     RECT  2.16 6.345 62.586 6.615 ;
     RECT  2.16 6.885 62.586 7.155 ;
     RECT  2.16 7.425 62.586 7.695 ;
     RECT  2.16 7.965 62.586 8.235 ;
     RECT  2.16 8.505 62.586 8.775 ;
     RECT  2.16 9.045 62.586 9.315 ;
     RECT  2.16 9.585 62.586 9.855 ;
     RECT  2.16 10.125 62.586 10.395 ;
     RECT  2.16 10.665 62.586 10.935 ;
     RECT  2.16 11.205 62.586 11.475 ;
     RECT  2.16 11.745 62.586 12.015 ;
     RECT  2.16 12.285 62.586 12.555 ;
     RECT  2.16 12.825 62.586 13.095 ;
     RECT  2.16 13.365 62.586 13.635 ;
     RECT  2.16 13.905 62.586 14.175 ;
     RECT  2.16 14.445 62.586 14.715 ;
     RECT  2.16 14.985 62.586 15.255 ;
     RECT  2.16 15.525 62.586 15.795 ;
     RECT  2.16 16.065 62.586 16.335 ;
     RECT  2.16 16.605 62.586 16.875 ;
     RECT  2.16 17.145 62.586 17.415 ;
     RECT  2.16 17.685 62.586 17.955 ;
     RECT  2.16 18.225 62.586 18.495 ;
     RECT  2.16 18.765 62.586 19.035 ;
     RECT  2.16 19.305 62.586 19.575 ;
     RECT  2.16 19.845 62.586 20.115 ;
     RECT  2.16 20.385 62.586 20.655 ;
     RECT  2.16 20.925 62.586 21.195 ;
     RECT  2.16 21.465 62.586 21.735 ;
     RECT  2.16 22.005 62.586 22.275 ;
     RECT  2.16 22.545 62.586 22.815 ;
     RECT  2.16 23.085 62.586 23.355 ;
     RECT  2.16 23.625 62.586 23.895 ;
     RECT  2.16 24.165 62.586 24.435 ;
     RECT  2.16 24.705 62.586 24.975 ;
     RECT  2.16 25.245 62.586 25.515 ;
     RECT  2.16 25.785 62.586 26.055 ;
     RECT  2.16 26.325 62.586 26.595 ;
     RECT  2.16 26.865 62.586 27.135 ;
     RECT  2.16 27.405 62.586 27.675 ;
    LAYER RVTP ;
     RECT  2.16 2.295 62.586 2.565 ;
     RECT  2.16 2.835 62.586 3.105 ;
     RECT  2.16 3.375 62.586 3.645 ;
     RECT  2.16 3.915 62.586 4.185 ;
     RECT  2.16 4.455 62.586 4.725 ;
     RECT  2.16 4.995 62.586 5.265 ;
     RECT  2.16 5.535 62.586 5.805 ;
     RECT  2.16 6.075 62.586 6.345 ;
     RECT  2.16 6.615 62.586 6.885 ;
     RECT  2.16 7.155 62.586 7.425 ;
     RECT  2.16 7.695 62.586 7.965 ;
     RECT  2.16 8.235 62.586 8.505 ;
     RECT  2.16 8.775 62.586 9.045 ;
     RECT  2.16 9.315 62.586 9.585 ;
     RECT  2.16 9.855 62.586 10.125 ;
     RECT  2.16 10.395 62.586 10.665 ;
     RECT  2.16 10.935 62.586 11.205 ;
     RECT  2.16 11.475 62.586 11.745 ;
     RECT  2.16 12.015 62.586 12.285 ;
     RECT  2.16 12.555 62.586 12.825 ;
     RECT  2.16 13.095 62.586 13.365 ;
     RECT  2.16 13.635 62.586 13.905 ;
     RECT  2.16 14.175 62.586 14.445 ;
     RECT  2.16 14.715 62.586 14.985 ;
     RECT  2.16 15.255 62.586 15.525 ;
     RECT  2.16 15.795 62.586 16.065 ;
     RECT  2.16 16.335 62.586 16.605 ;
     RECT  2.16 16.875 62.586 17.145 ;
     RECT  2.16 17.415 62.586 17.685 ;
     RECT  2.16 17.955 62.586 18.225 ;
     RECT  2.16 18.495 62.586 18.765 ;
     RECT  2.16 19.035 62.586 19.305 ;
     RECT  2.16 19.575 62.586 19.845 ;
     RECT  2.16 20.115 62.586 20.385 ;
     RECT  2.16 20.655 62.586 20.925 ;
     RECT  2.16 21.195 62.586 21.465 ;
     RECT  2.16 21.735 62.586 22.005 ;
     RECT  2.16 22.275 62.586 22.545 ;
     RECT  2.16 22.815 62.586 23.085 ;
     RECT  2.16 23.355 62.586 23.625 ;
     RECT  2.16 23.895 62.586 24.165 ;
     RECT  2.16 24.435 62.586 24.705 ;
     RECT  2.16 24.975 62.586 25.245 ;
     RECT  2.16 25.515 62.586 25.785 ;
     RECT  2.16 26.055 62.586 26.325 ;
     RECT  2.16 26.595 62.586 26.865 ;
     RECT  2.16 27.135 62.586 27.405 ;
     RECT  2.16 27.675 62.586 27.81 ;
    LAYER M1 ;
     RECT  2.16 2.151 62.586 27.819 ;
    LAYER M2 ;
     RECT  0.103 10.332 2.16 10.35 ;
     RECT  21.775 29.961 21.847 29.979 ;
     RECT  21.847 29.961 21.875 30.168 ;
     RECT  21.875 30.042 21.983 30.168 ;
     RECT  2.16 2.151 22.063 27.819 ;
     RECT  22.063 2.151 22.415 28.476 ;
     RECT  21.983 30.078 22.739 30.168 ;
     RECT  22.739 30.15 23.503 30.168 ;
     RECT  23.503 30.078 23.603 30.168 ;
     RECT  23.603 30.15 23.819 30.168 ;
     RECT  26.383 29.961 26.455 29.979 ;
     RECT  26.491 28.962 26.563 28.98 ;
     RECT  26.563 28.962 26.591 29.052 ;
     RECT  26.591 29.034 26.663 29.052 ;
     RECT  26.455 29.961 26.771 30.168 ;
     RECT  22.415 2.151 26.887 27.819 ;
     RECT  26.771 30.042 27.607 30.168 ;
     RECT  27.607 29.034 27.815 29.052 ;
     RECT  27.607 30.006 27.967 30.168 ;
     RECT  26.887 2.151 28.111 27.936 ;
     RECT  27.967 29.961 28.319 30.168 ;
     RECT  28.319 29.961 28.427 30.06 ;
     RECT  28.427 30.042 28.499 30.06 ;
     RECT  28.111 2.151 29.255 28.008 ;
     RECT  29.255 2.151 31.127 27.864 ;
     RECT  31.127 2.151 39.091 27.819 ;
     RECT  39.091 2.151 39.811 27.864 ;
     RECT  39.811 2.151 40.279 27.936 ;
     RECT  40.531 30.15 40.675 30.168 ;
     RECT  41.179 29.034 41.423 29.052 ;
     RECT  40.675 30.078 41.647 30.168 ;
     RECT  41.647 30.006 41.719 30.168 ;
     RECT  41.719 29.916 41.855 30.168 ;
     RECT  41.855 29.961 41.963 30.168 ;
     RECT  41.963 30.006 42.107 30.168 ;
     RECT  40.279 2.151 42.683 28.008 ;
     RECT  42.871 29.034 42.943 29.052 ;
     RECT  42.107 30.078 43.087 30.168 ;
     RECT  42.943 28.962 43.259 29.052 ;
     RECT  42.683 2.151 43.555 27.936 ;
     RECT  43.555 2.151 43.655 28.008 ;
     RECT  43.087 29.961 44.123 30.168 ;
     RECT  43.655 2.151 44.671 27.9 ;
     RECT  44.167 29.034 44.743 29.052 ;
     RECT  44.123 30.006 44.879 30.168 ;
     RECT  44.879 30.006 44.915 30.096 ;
     RECT  44.915 30.078 45.023 30.096 ;
     RECT  44.743 28.962 45.203 29.052 ;
     RECT  45.203 29.034 45.347 29.052 ;
     RECT  44.671 2.151 46.463 27.936 ;
     RECT  46.463 2.151 48.011 27.9 ;
     RECT  48.011 2.151 62.586 27.819 ;
     RECT  62.586 19.35 62.699 21.258 ;
     RECT  62.586 7.128 63.311 13.194 ;
     RECT  62.699 19.62 63.311 21.258 ;
     RECT  62.586 27.18 63.311 27.198 ;
     RECT  63.311 20.16 63.347 21.186 ;
     RECT  63.347 20.43 63.491 21.186 ;
     RECT  63.311 7.128 63.887 8.262 ;
     RECT  63.311 9.396 63.887 13.194 ;
     RECT  62.586 18.54 63.887 18.558 ;
     RECT  62.586 22.05 63.887 24.264 ;
     RECT  62.586 25.254 63.887 26.118 ;
     RECT  63.887 7.128 63.923 8.064 ;
     RECT  63.887 9.864 63.923 10.188 ;
     RECT  63.491 21.168 63.923 21.186 ;
     RECT  63.887 22.086 63.923 22.914 ;
     RECT  63.887 25.254 63.923 25.884 ;
     RECT  63.923 7.128 63.959 7.794 ;
     RECT  63.923 9.864 63.959 10.08 ;
     RECT  63.887 11.556 63.959 12.816 ;
     RECT  63.923 25.326 63.959 25.344 ;
     RECT  63.959 11.556 63.995 11.772 ;
     RECT  63.923 22.086 63.995 22.302 ;
     RECT  63.995 11.754 64.031 11.772 ;
     RECT  63.995 22.284 64.031 22.302 ;
     RECT  63.959 12.798 64.679 12.816 ;
     RECT  64.651 8.442 64.751 9.189 ;
     RECT  64.651 24.948 64.751 24.966 ;
    LAYER M3 ;
     RECT  2.415 2.143 2.505 2.413 ;
     RECT  5.115 2.143 5.205 2.413 ;
     RECT  7.815 2.143 7.905 2.413 ;
     RECT  10.515 2.143 10.605 2.413 ;
     RECT  13.215 2.143 13.305 2.413 ;
     RECT  15.915 2.143 16.005 2.413 ;
     RECT  18.615 2.143 18.705 2.413 ;
     RECT  21.315 2.143 21.405 2.413 ;
     RECT  24.015 2.143 24.105 2.413 ;
     RECT  26.715 2.143 26.805 2.413 ;
     RECT  29.415 2.143 29.505 2.413 ;
     RECT  32.115 2.143 32.205 2.413 ;
     RECT  34.815 2.143 34.905 2.413 ;
     RECT  37.515 2.143 37.605 2.413 ;
     RECT  40.215 2.143 40.305 2.413 ;
     RECT  42.915 2.143 43.005 2.413 ;
     RECT  45.615 2.143 45.705 2.413 ;
     RECT  48.315 2.143 48.405 2.413 ;
     RECT  51.015 2.143 51.105 2.413 ;
     RECT  53.715 2.143 53.805 2.413 ;
     RECT  56.415 2.143 56.505 2.413 ;
     RECT  59.115 2.143 59.205 2.413 ;
     RECT  61.815 2.143 61.905 2.413 ;
     RECT  63.864 6.859 63.882 6.955 ;
     RECT  59.115 2.413 59.397 6.961 ;
     RECT  45.615 2.413 45.897 7.051 ;
     RECT  46.764 6.961 46.782 7.051 ;
     RECT  51.015 2.413 51.297 7.051 ;
     RECT  58.788 6.961 59.397 7.051 ;
     RECT  61.815 2.413 62.097 7.051 ;
     RECT  63.864 6.955 63.954 7.051 ;
     RECT  52.704 6.961 52.722 7.079 ;
     RECT  42.915 2.413 43.197 7.087 ;
     RECT  56.415 2.413 56.697 7.087 ;
     RECT  63.828 7.051 63.954 7.147 ;
     RECT  56.412 7.087 56.697 7.187 ;
     RECT  42.876 7.087 43.197 7.195 ;
     RECT  45.615 7.051 46.782 7.195 ;
     RECT  51.015 7.051 51.678 7.195 ;
     RECT  53.715 2.413 53.997 7.195 ;
     RECT  54.792 6.961 54.81 7.195 ;
     RECT  58.32 7.051 59.397 7.195 ;
     RECT  38.808 7.087 38.826 7.223 ;
     RECT  37.515 2.413 37.797 7.231 ;
     RECT  42.84 7.195 43.197 7.231 ;
     RECT  50.724 7.195 51.678 7.231 ;
     RECT  42.804 7.231 43.197 7.291 ;
     RECT  40.215 2.413 40.497 7.321 ;
     RECT  53.715 7.195 54.81 7.321 ;
     RECT  58.248 7.195 59.397 7.321 ;
     RECT  58.176 7.321 59.397 7.339 ;
     RECT  45.432 7.195 46.854 7.349 ;
     RECT  50.724 7.231 51.786 7.349 ;
     RECT  50.724 7.349 51.678 7.385 ;
     RECT  58.14 7.339 59.397 7.385 ;
     RECT  58.176 7.385 59.397 7.429 ;
     RECT  58.176 7.429 59.418 7.529 ;
     RECT  61.815 7.051 62.37 7.579 ;
     RECT  40.215 7.321 40.914 7.591 ;
     RECT  50.724 7.385 51.297 7.591 ;
     RECT  52.74 7.321 54.81 7.619 ;
     RECT  61.815 7.579 62.73 7.627 ;
     RECT  63.792 7.147 63.954 7.627 ;
     RECT  42.768 7.291 43.197 7.663 ;
     RECT  45.615 7.349 46.854 7.735 ;
     RECT  52.992 7.619 54.81 7.763 ;
     RECT  42.588 7.663 43.197 7.771 ;
     RECT  61.815 7.627 63.954 7.799 ;
     RECT  39.78 7.591 40.914 7.861 ;
     RECT  58.644 7.529 59.418 7.861 ;
     RECT  60.336 7.501 60.354 7.861 ;
     RECT  45.615 7.735 47.034 7.933 ;
     RECT  58.644 7.861 60.354 7.963 ;
     RECT  53.715 7.763 54.81 7.969 ;
     RECT  61.815 7.799 63.918 8.005 ;
     RECT  56.415 7.187 56.697 8.041 ;
     RECT  61.668 8.005 63.918 8.069 ;
     RECT  58.644 7.963 60.426 8.131 ;
     RECT  61.668 8.069 63.882 8.267 ;
     RECT  45.615 7.933 47.25 8.303 ;
     RECT  50.688 7.591 51.297 8.311 ;
     RECT  57.78 8.239 57.798 8.311 ;
     RECT  58.644 8.131 60.534 8.311 ;
     RECT  61.668 8.267 63.342 8.347 ;
     RECT  42.588 7.771 43.326 8.401 ;
     RECT  47.232 8.303 47.25 8.401 ;
     RECT  49.788 8.203 49.806 8.429 ;
     RECT  64.656 8.395 64.674 8.437 ;
     RECT  57.78 8.311 60.534 8.465 ;
     RECT  26.715 2.413 26.997 8.491 ;
     RECT  57.78 8.465 59.922 8.537 ;
     RECT  26.715 8.491 27.198 8.581 ;
     RECT  39.78 7.861 41.022 8.581 ;
     RECT  44.352 8.311 44.37 8.581 ;
     RECT  50.688 8.311 51.714 8.581 ;
     RECT  24.015 2.413 24.297 8.671 ;
     RECT  42.588 8.401 43.542 8.671 ;
     RECT  39.78 8.581 41.454 8.683 ;
     RECT  42.264 8.671 43.542 8.683 ;
     RECT  26.715 8.581 28.062 8.707 ;
     RECT  29.415 2.413 29.697 8.707 ;
     RECT  30.636 8.671 30.654 8.707 ;
     RECT  50.436 8.581 51.822 8.707 ;
     RECT  32.115 2.413 32.397 8.743 ;
     RECT  34.815 2.413 35.097 8.743 ;
     RECT  60.66 8.491 60.75 8.779 ;
     RECT  61.56 8.347 63.342 8.779 ;
     RECT  29.196 8.707 29.697 8.815 ;
     RECT  30.492 8.707 30.654 8.815 ;
     RECT  32.115 8.743 32.526 8.815 ;
     RECT  39.78 8.683 43.542 8.815 ;
     RECT  44.352 8.581 44.874 8.815 ;
     RECT  32.115 8.815 32.67 8.851 ;
     RECT  33.444 8.743 33.462 8.851 ;
     RECT  53.715 7.969 55.278 8.851 ;
     RECT  56.088 8.041 56.697 8.851 ;
     RECT  29.196 8.815 29.754 8.941 ;
     RECT  30.492 8.815 31.338 8.941 ;
     RECT  34.815 8.743 35.802 8.941 ;
     RECT  48.315 2.413 48.597 8.941 ;
     RECT  53.715 8.851 56.697 8.977 ;
     RECT  53.028 8.977 56.697 9.005 ;
     RECT  23.976 8.671 24.297 9.013 ;
     RECT  39.78 8.815 44.874 9.049 ;
     RECT  45.615 8.303 46.422 9.049 ;
     RECT  48.315 8.941 49.05 9.049 ;
     RECT  23.976 9.013 24.354 9.067 ;
     RECT  23.364 9.067 24.354 9.085 ;
     RECT  29.196 8.941 31.374 9.085 ;
     RECT  32.115 8.851 33.57 9.085 ;
     RECT  34.815 8.941 36.018 9.085 ;
     RECT  23.364 9.085 24.642 9.113 ;
     RECT  53.028 9.005 55.602 9.113 ;
     RECT  25.848 9.085 25.866 9.121 ;
     RECT  34.74 9.085 36.018 9.121 ;
     RECT  37.515 7.231 37.962 9.121 ;
     RECT  39.78 9.049 46.422 9.121 ;
     RECT  47.232 8.401 47.43 9.121 ;
     RECT  48.24 9.049 49.05 9.121 ;
     RECT  57.6 8.779 57.618 9.121 ;
     RECT  64.656 8.437 64.746 9.197 ;
     RECT  38.7 7.231 38.754 9.211 ;
     RECT  39.672 9.121 49.05 9.211 ;
     RECT  50.436 8.707 52.038 9.211 ;
     RECT  52.812 9.121 52.974 9.211 ;
     RECT  64.728 9.197 64.746 9.245 ;
     RECT  21.315 2.413 21.597 9.247 ;
     RECT  34.74 9.121 36.234 9.247 ;
     RECT  37.044 9.121 37.962 9.247 ;
     RECT  38.7 9.211 49.518 9.247 ;
     RECT  50.436 9.211 52.974 9.247 ;
     RECT  23.616 9.113 24.642 9.259 ;
     RECT  56.376 9.005 56.697 9.275 ;
     RECT  25.848 9.121 25.974 9.283 ;
     RECT  26.715 8.707 28.098 9.283 ;
     RECT  60.66 8.779 63.342 9.293 ;
     RECT  23.616 9.259 24.75 9.311 ;
     RECT  61.668 9.293 63.342 9.311 ;
     RECT  25.848 9.283 28.098 9.355 ;
     RECT  58.572 8.537 59.922 9.355 ;
     RECT  60.66 9.293 60.93 9.355 ;
     RECT  61.74 9.311 63.342 9.355 ;
     RECT  57.564 9.121 57.618 9.391 ;
     RECT  23.616 9.311 24.678 9.509 ;
     RECT  2.415 2.413 2.697 9.517 ;
     RECT  13.215 2.413 13.497 9.517 ;
     RECT  29.052 9.085 33.606 9.517 ;
     RECT  53.715 9.113 55.602 9.533 ;
     RECT  58.572 9.355 60.93 9.545 ;
     RECT  21.315 9.247 21.978 9.553 ;
     RECT  3.852 9.481 3.87 9.581 ;
     RECT  57.564 9.391 57.654 9.581 ;
     RECT  61.74 9.355 63.882 9.581 ;
     RECT  25.524 9.355 28.134 9.589 ;
     RECT  56.415 9.275 56.697 9.589 ;
     RECT  29.052 9.517 33.858 9.625 ;
     RECT  34.74 9.247 37.962 9.625 ;
     RECT  56.415 9.589 56.754 9.625 ;
     RECT  56.415 9.625 56.79 9.643 ;
     RECT  63.252 9.581 63.882 9.643 ;
     RECT  53.715 9.533 55.242 9.653 ;
     RECT  5.115 2.413 5.397 9.661 ;
     RECT  56.415 9.643 56.934 9.689 ;
     RECT  7.815 2.413 8.097 9.751 ;
     RECT  29.052 9.625 37.962 9.751 ;
     RECT  38.7 9.247 52.974 9.751 ;
     RECT  58.572 9.545 59.454 9.779 ;
     RECT  60.192 9.545 60.93 9.779 ;
     RECT  21.315 9.553 22.338 9.787 ;
     RECT  58.572 9.779 59.397 9.787 ;
     RECT  5.115 9.661 6.03 9.859 ;
     RECT  10.515 2.413 10.797 9.883 ;
     RECT  4.788 9.859 6.03 9.895 ;
     RECT  21.315 9.787 22.374 9.895 ;
     RECT  0.18 9.739 0.198 9.917 ;
     RECT  56.415 9.689 56.862 9.923 ;
     RECT  21.315 9.895 22.482 9.931 ;
     RECT  29.052 9.751 52.974 9.931 ;
     RECT  53.715 9.653 53.997 9.931 ;
     RECT  54.72 9.653 55.242 9.959 ;
     RECT  60.192 9.779 60.462 9.959 ;
     RECT  21.276 9.931 22.482 10.021 ;
     RECT  13.215 9.517 14.022 10.057 ;
     RECT  61.74 9.581 62.406 10.057 ;
     RECT  21.276 10.021 22.842 10.075 ;
     RECT  29.052 9.931 53.997 10.085 ;
     RECT  3.492 9.931 3.51 10.121 ;
     RECT  14.76 10.093 14.778 10.129 ;
     RECT  15.915 2.413 16.197 10.129 ;
     RECT  58.14 9.787 59.397 10.157 ;
     RECT  20.844 10.075 22.842 10.201 ;
     RECT  23.616 9.509 24.642 10.201 ;
     RECT  63.252 9.643 63.954 10.219 ;
     RECT  4.248 9.895 6.03 10.229 ;
     RECT  6.804 9.859 6.822 10.229 ;
     RECT  2.304 9.517 2.697 10.253 ;
     RECT  4.248 10.229 4.266 10.253 ;
     RECT  9.54 9.859 9.558 10.291 ;
     RECT  10.332 9.883 10.797 10.291 ;
     RECT  20.844 10.201 24.642 10.291 ;
     RECT  61.704 10.057 62.406 10.291 ;
     RECT  61.344 10.291 62.406 10.315 ;
     RECT  63.252 10.219 64.674 10.315 ;
     RECT  25.524 9.589 28.17 10.327 ;
     RECT  29.052 10.085 51.642 10.327 ;
     RECT  0.108 9.931 0.126 10.355 ;
     RECT  9.54 10.291 11.646 10.363 ;
     RECT  12.888 10.057 14.022 10.363 ;
     RECT  14.76 10.129 16.197 10.363 ;
     RECT  20.844 10.291 24.786 10.363 ;
     RECT  25.524 10.327 51.642 10.363 ;
     RECT  9.54 10.363 12.006 10.471 ;
     RECT  56.415 9.923 56.697 10.471 ;
     RECT  60.3 9.959 60.462 10.561 ;
     RECT  61.344 10.315 64.674 10.561 ;
     RECT  60.3 10.561 64.674 10.589 ;
     RECT  60.444 10.589 64.674 10.637 ;
     RECT  55.224 9.959 55.242 10.651 ;
     RECT  56.196 10.471 56.697 10.651 ;
     RECT  5.115 10.229 6.03 10.661 ;
     RECT  7.815 9.751 8.55 10.697 ;
     RECT  9.54 10.471 12.042 10.733 ;
     RECT  7.815 10.697 8.118 10.741 ;
     RECT  12.888 10.363 16.197 10.741 ;
     RECT  20.844 10.363 51.642 10.831 ;
     RECT  52.38 10.085 53.997 10.831 ;
     RECT  20.844 10.831 53.997 10.931 ;
     RECT  55.224 10.651 56.697 10.931 ;
     RECT  58.14 10.157 58.158 10.931 ;
     RECT  9.54 10.733 11.826 10.975 ;
     RECT  12.564 10.741 16.197 10.975 ;
     RECT  9 10.975 11.826 11.003 ;
     RECT  12.564 10.975 16.47 11.011 ;
     RECT  9 11.003 11.466 11.021 ;
     RECT  9.54 11.021 11.466 11.039 ;
     RECT  59.115 10.157 59.397 11.173 ;
     RECT  12.564 11.011 16.542 11.201 ;
     RECT  54.72 10.975 54.81 11.237 ;
     RECT  20.844 10.931 51.894 11.261 ;
     RECT  12.6 11.201 16.542 11.281 ;
     RECT  20.844 11.261 51.822 11.309 ;
     RECT  7.416 10.741 8.118 11.399 ;
     RECT  9.612 11.039 11.466 11.399 ;
     RECT  58.716 11.173 59.397 11.399 ;
     RECT  60.444 10.637 63.918 11.399 ;
     RECT  7.416 11.399 8.097 11.435 ;
     RECT  52.668 10.931 53.997 11.443 ;
     RECT  54.72 11.237 54.738 11.443 ;
     RECT  58.752 11.399 59.397 11.443 ;
     RECT  60.84 11.399 63.918 11.467 ;
     RECT  64.656 10.637 64.674 11.467 ;
     RECT  55.872 10.931 56.697 11.479 ;
     RECT  55.872 11.479 56.754 11.579 ;
     RECT  55.944 11.579 56.754 11.641 ;
     RECT  55.944 11.641 56.79 11.659 ;
     RECT  55.944 11.659 57.186 11.704 ;
     RECT  58.752 11.443 60.102 11.705 ;
     RECT  55.944 11.704 57.87 11.741 ;
     RECT  12.6 11.281 16.686 11.821 ;
     RECT  18.615 2.413 18.897 11.911 ;
     RECT  20.844 11.309 51.786 11.939 ;
     RECT  9.972 11.399 11.466 11.947 ;
     RECT  12.6 11.821 16.902 11.947 ;
     RECT  20.916 11.939 51.786 11.975 ;
     RECT  55.944 11.741 57.69 11.975 ;
     RECT  9.972 11.947 16.902 11.983 ;
     RECT  20.916 11.975 49.086 12.083 ;
     RECT  49.86 11.975 51.786 12.091 ;
     RECT  52.668 11.443 54.738 12.091 ;
     RECT  49.86 12.091 54.738 12.181 ;
     RECT  9.972 11.983 17.046 12.217 ;
     RECT  49.86 12.181 54.81 12.245 ;
     RECT  18.216 11.911 18.897 12.253 ;
     RECT  54.792 12.245 54.81 12.253 ;
     RECT  49.86 12.245 54.054 12.281 ;
     RECT  60.84 11.467 64.674 12.317 ;
     RECT  18.216 12.253 19.458 12.325 ;
     RECT  54.792 12.253 54.882 12.353 ;
     RECT  18.216 12.325 19.674 12.361 ;
     RECT  58.752 11.705 59.397 12.361 ;
     RECT  54.864 12.353 54.882 12.389 ;
     RECT  18 12.361 19.674 12.451 ;
     RECT  60.84 12.317 63.918 12.509 ;
     RECT  18 12.451 19.746 12.515 ;
     RECT  9.972 12.217 17.154 12.523 ;
     RECT  63.288 12.509 63.918 12.623 ;
     RECT  63.288 12.623 63.882 12.659 ;
     RECT  21.096 12.083 49.086 12.748 ;
     RECT  60.84 12.509 62.442 12.749 ;
     RECT  21.096 12.748 49.122 12.793 ;
     RECT  49.86 12.281 53.997 12.793 ;
     RECT  64.656 12.317 64.674 12.821 ;
     RECT  61.524 12.749 62.442 12.893 ;
     RECT  18.615 12.515 19.746 12.901 ;
     RECT  56.415 11.975 57.69 13.019 ;
     RECT  9.972 12.523 17.694 13.055 ;
     RECT  56.415 13.019 57.546 13.055 ;
     RECT  58.716 12.361 59.397 13.091 ;
     RECT  63.864 12.659 63.882 13.199 ;
     RECT  56.415 13.055 57.006 13.325 ;
     RECT  58.284 13.171 58.302 13.325 ;
     RECT  54.72 13.261 54.738 13.397 ;
     RECT  61.668 12.893 62.442 13.397 ;
     RECT  21.096 12.793 53.997 13.405 ;
     RECT  18.615 12.901 19.962 13.531 ;
     RECT  10.515 13.055 17.694 13.613 ;
     RECT  21.024 13.405 53.997 13.627 ;
     RECT  18.615 13.531 19.998 13.639 ;
     RECT  21.024 13.627 54.378 13.639 ;
     RECT  61.668 13.397 62.37 13.639 ;
     RECT  11.7 13.613 17.694 13.865 ;
     RECT  60.948 13.639 62.37 13.901 ;
     RECT  18.615 13.639 54.378 14.143 ;
     RECT  56.415 13.325 56.97 14.243 ;
     RECT  18.615 14.143 54.45 14.251 ;
     RECT  18.615 14.251 54.486 14.377 ;
     RECT  55.548 14.251 55.566 14.377 ;
     RECT  10.515 13.613 10.797 14.449 ;
     RECT  11.7 13.865 16.866 14.449 ;
     RECT  18.615 14.377 55.566 14.639 ;
     RECT  61.668 13.901 62.37 14.791 ;
     RECT  10.515 14.449 16.866 14.819 ;
     RECT  11.556 14.819 16.866 14.915 ;
     RECT  19.656 14.639 55.566 14.945 ;
     RECT  11.7 14.915 16.866 15.025 ;
     RECT  17.676 13.865 17.694 15.025 ;
     RECT  59.115 13.091 59.397 15.025 ;
     RECT  11.7 15.025 17.694 15.179 ;
     RECT  58.716 15.025 59.397 15.179 ;
     RECT  19.656 14.945 54.774 15.215 ;
     RECT  55.584 15.025 55.602 15.251 ;
     RECT  61.236 14.791 62.37 15.323 ;
     RECT  18.615 14.639 18.897 15.457 ;
     RECT  19.656 15.215 35.658 15.457 ;
     RECT  11.916 15.179 17.694 15.533 ;
     RECT  11.988 15.533 17.694 15.565 ;
     RECT  18.615 15.457 35.658 15.565 ;
     RECT  61.236 15.323 62.097 16.075 ;
     RECT  60.624 16.075 62.097 16.133 ;
     RECT  11.988 15.565 35.658 16.141 ;
     RECT  60.624 16.133 60.642 16.169 ;
     RECT  36.468 15.215 54.774 16.331 ;
     RECT  55.584 16.363 55.602 16.411 ;
     RECT  54.864 16.411 55.602 16.501 ;
     RECT  56.415 14.243 56.697 16.501 ;
     RECT  11.988 16.141 35.73 16.507 ;
     RECT  36.468 16.331 54.09 16.507 ;
     RECT  11.988 16.507 54.09 16.835 ;
     RECT  54.864 16.501 56.697 16.835 ;
     RECT  61.815 16.133 62.097 17.041 ;
     RECT  36.468 16.835 54.09 17.077 ;
     RECT  61.815 17.041 62.262 17.347 ;
     RECT  59.115 15.179 59.397 17.455 ;
     RECT  61.815 17.347 62.442 17.491 ;
     RECT  36.468 17.077 54.306 17.653 ;
     RECT  55.044 16.835 56.697 17.653 ;
     RECT  11.988 16.835 35.658 17.761 ;
     RECT  36.468 17.653 56.697 17.761 ;
     RECT  11.988 17.761 56.697 17.923 ;
     RECT  57.924 17.725 57.942 17.923 ;
     RECT  59.115 17.455 59.562 17.923 ;
     RECT  61.56 17.491 62.442 17.923 ;
     RECT  57.924 17.923 59.562 17.995 ;
     RECT  57.924 17.995 59.778 18.121 ;
     RECT  11.988 17.923 57.114 18.157 ;
     RECT  57.924 18.121 60.426 18.157 ;
     RECT  11.988 18.157 60.426 18.265 ;
     RECT  61.2 17.923 62.442 18.265 ;
     RECT  11.988 18.265 62.442 18.301 ;
     RECT  11.52 18.301 62.442 18.563 ;
     RECT  11.52 18.563 59.397 18.689 ;
     RECT  60.444 18.563 62.442 19.003 ;
     RECT  60.444 19.003 62.478 19.345 ;
     RECT  60.444 19.345 62.694 19.381 ;
     RECT  11.52 18.689 54.162 19.543 ;
     RECT  54.972 18.689 59.397 19.543 ;
     RECT  60.336 19.381 62.694 19.615 ;
     RECT  63.864 18.535 63.882 19.615 ;
     RECT  60.336 19.615 63.882 19.777 ;
     RECT  60.228 19.777 63.882 19.949 ;
     RECT  10.515 14.819 10.797 19.963 ;
     RECT  11.52 19.543 59.397 19.963 ;
     RECT  10.515 19.963 59.397 20.353 ;
     RECT  60.228 19.949 63.486 20.353 ;
     RECT  10.515 20.353 63.486 21.163 ;
     RECT  10.515 21.163 63.918 21.505 ;
     RECT  9.504 21.631 9.522 21.667 ;
     RECT  10.26 21.505 63.918 21.667 ;
     RECT  9.504 21.667 63.918 21.775 ;
     RECT  9.288 21.775 63.918 22.081 ;
     RECT  9.288 22.081 63.99 22.279 ;
     RECT  7.815 11.435 8.097 23.125 ;
     RECT  9.288 22.279 64.026 23.161 ;
     RECT  9.18 23.161 64.026 23.309 ;
     RECT  9.18 23.309 63.918 23.515 ;
     RECT  9.108 23.515 63.918 23.549 ;
     RECT  7.815 23.125 8.37 23.585 ;
     RECT  15.768 23.549 63.918 23.597 ;
     RECT  9.108 23.549 14.742 23.693 ;
     RECT  15.768 23.597 63.882 23.729 ;
     RECT  15.768 23.729 62.874 23.885 ;
     RECT  9.144 23.693 14.742 24.173 ;
     RECT  15.768 23.885 62.802 24.427 ;
     RECT  9.144 24.173 14.634 24.745 ;
     RECT  15.696 24.427 62.802 24.797 ;
     RECT  7.815 23.585 8.19 24.871 ;
     RECT  9 24.745 14.634 24.871 ;
     RECT  15.696 24.797 62.442 24.907 ;
     RECT  15.588 24.907 62.442 24.943 ;
     RECT  64.656 24.907 64.674 24.943 ;
     RECT  64.656 24.943 64.746 24.971 ;
     RECT  15.48 24.943 62.442 24.979 ;
     RECT  64.728 24.971 64.746 24.989 ;
     RECT  63.864 23.729 63.882 25.099 ;
     RECT  7.815 24.871 14.634 25.141 ;
     RECT  15.408 24.979 62.442 25.141 ;
     RECT  63.864 25.099 63.918 25.195 ;
     RECT  63.864 25.195 63.954 25.285 ;
     RECT  63.828 25.285 63.954 25.349 ;
     RECT  63.828 25.349 63.918 25.771 ;
     RECT  7.815 25.141 62.442 25.805 ;
     RECT  7.815 25.805 57.762 25.817 ;
     RECT  58.5 25.805 62.442 25.867 ;
     RECT  63.288 25.771 63.918 25.867 ;
     RECT  58.5 25.867 63.918 25.889 ;
     RECT  58.5 25.889 63.882 26.051 ;
     RECT  58.5 26.051 62.37 26.093 ;
     RECT  63.288 26.051 63.882 26.123 ;
     RECT  60.984 26.093 62.37 26.249 ;
     RECT  61.452 26.249 62.37 26.285 ;
     RECT  7.815 25.817 57.726 26.519 ;
     RECT  61.524 26.285 62.37 26.519 ;
     RECT  61.704 26.519 62.37 26.555 ;
     RECT  9.036 26.519 57.726 26.731 ;
     RECT  58.5 26.093 60.174 26.731 ;
     RECT  61.815 26.555 62.37 26.789 ;
     RECT  9.036 26.731 60.174 26.825 ;
     RECT  34.815 26.825 60.174 26.933 ;
     RECT  9.036 26.825 33.822 27.059 ;
     RECT  34.815 26.933 37.797 27.059 ;
     RECT  61.815 26.789 62.262 27.059 ;
     RECT  9.864 27.059 33.822 27.095 ;
     RECT  34.815 27.059 36.018 27.095 ;
     RECT  9.864 27.095 19.926 27.131 ;
     RECT  34.815 27.095 35.874 27.131 ;
     RECT  20.988 27.095 33.822 27.167 ;
     RECT  38.664 26.933 60.174 27.167 ;
     RECT  52.308 27.167 60.174 27.175 ;
     RECT  63.288 26.123 63.306 27.203 ;
     RECT  9.864 27.131 18.897 27.329 ;
     RECT  20.988 27.167 33.03 27.329 ;
     RECT  33.804 27.167 33.822 27.329 ;
     RECT  34.815 27.131 35.766 27.329 ;
     RECT  52.308 27.175 60.354 27.329 ;
     RECT  9.864 27.329 10.854 27.365 ;
     RECT  12.708 27.329 16.218 27.365 ;
     RECT  17.244 27.329 18.897 27.365 ;
     RECT  21.06 27.329 32.886 27.365 ;
     RECT  34.815 27.329 35.694 27.365 ;
     RECT  54.792 27.329 60.354 27.365 ;
     RECT  38.664 27.167 51.297 27.401 ;
     RECT  54.792 27.365 57.51 27.401 ;
     RECT  58.392 27.365 60.354 27.437 ;
     RECT  38.664 27.401 50.238 27.473 ;
     RECT  54.792 27.401 56.697 27.473 ;
     RECT  21.06 27.365 32.397 27.509 ;
     RECT  49.536 27.473 49.95 27.509 ;
     RECT  2.415 10.253 2.697 27.557 ;
     RECT  5.115 10.661 5.397 27.557 ;
     RECT  7.815 26.519 8.097 27.557 ;
     RECT  25.38 27.509 32.397 27.557 ;
     RECT  34.815 27.365 35.097 27.557 ;
     RECT  37.515 27.059 37.797 27.557 ;
     RECT  51.015 27.401 51.297 27.557 ;
     RECT  59.115 27.437 60.354 27.557 ;
     RECT  61.815 27.059 62.097 27.557 ;
     RECT  9.864 27.365 10.797 27.599 ;
     RECT  12.708 27.365 14.958 27.599 ;
     RECT  15.732 27.365 16.218 27.599 ;
     RECT  21.06 27.509 24.39 27.599 ;
     RECT  25.38 27.557 31.554 27.599 ;
     RECT  54.792 27.473 54.918 27.599 ;
     RECT  55.764 27.473 56.697 27.599 ;
     RECT  10.116 27.599 10.797 27.635 ;
     RECT  12.708 27.599 13.698 27.635 ;
     RECT  16.056 27.599 16.197 27.635 ;
     RECT  18.288 27.365 18.897 27.635 ;
     RECT  26.028 27.599 31.554 27.635 ;
     RECT  38.664 27.473 48.597 27.635 ;
     RECT  52.308 27.329 53.997 27.635 ;
     RECT  54.792 27.599 54.81 27.635 ;
     RECT  55.944 27.599 56.697 27.635 ;
     RECT  59.307 27.557 60.354 27.671 ;
     RECT  49.932 27.509 49.95 27.707 ;
     RECT  52.308 27.635 52.974 27.707 ;
     RECT  10.368 27.635 10.797 27.743 ;
     RECT  52.956 27.707 52.974 27.743 ;
     RECT  57.492 27.401 57.51 27.743 ;
     RECT  59.307 27.671 59.922 27.743 ;
     RECT  19.908 27.131 19.926 27.779 ;
     RECT  26.244 27.635 29.754 27.779 ;
     RECT  39.096 27.635 48.597 27.779 ;
     RECT  2.607 27.557 2.697 27.827 ;
     RECT  5.307 27.557 5.397 27.827 ;
     RECT  8.007 27.557 8.097 27.827 ;
     RECT  10.707 27.743 10.797 27.827 ;
     RECT  13.407 27.635 13.497 27.827 ;
     RECT  16.107 27.635 16.197 27.827 ;
     RECT  18.807 27.635 18.897 27.827 ;
     RECT  21.507 27.599 24.297 27.827 ;
     RECT  26.244 27.779 29.697 27.827 ;
     RECT  32.307 27.557 32.397 27.827 ;
     RECT  35.007 27.557 35.097 27.827 ;
     RECT  37.707 27.557 37.797 27.827 ;
     RECT  39.096 27.779 46.458 27.827 ;
     RECT  47.664 27.779 48.597 27.827 ;
     RECT  51.207 27.557 51.297 27.827 ;
     RECT  53.907 27.635 53.997 27.827 ;
     RECT  56.607 27.635 56.697 27.827 ;
     RECT  59.307 27.743 59.397 27.827 ;
     RECT  62.007 27.557 62.097 27.827 ;
     RECT  31.104 27.635 31.122 27.869 ;
     RECT  39.096 27.827 45.342 27.869 ;
     RECT  47.664 27.827 48.006 27.869 ;
     RECT  26.244 27.827 29.25 27.905 ;
     RECT  47.988 27.869 48.006 27.905 ;
     RECT  29.196 27.905 29.25 27.941 ;
     RECT  39.816 27.869 45.342 27.941 ;
     RECT  46.44 27.827 46.458 27.941 ;
     RECT  29.232 27.941 29.25 28.013 ;
     RECT  39.924 27.941 45.342 29.021 ;
     RECT  40.176 29.021 45.342 29.057 ;
     RECT  26.244 27.905 28.422 30.037 ;
     RECT  40.176 29.057 45.198 30.173 ;
     RECT  21.636 27.827 23.886 30.179 ;
     RECT  21.654 30.179 21.708 30.204 ;
     RECT  21.726 30.179 21.78 30.204 ;
     RECT  21.798 30.179 21.852 30.204 ;
     RECT  21.87 30.179 21.924 30.204 ;
     RECT  21.942 30.179 21.996 30.204 ;
     RECT  22.014 30.179 22.068 30.204 ;
     RECT  22.086 30.179 22.14 30.204 ;
     RECT  22.158 30.179 22.212 30.204 ;
     RECT  22.23 30.179 22.284 30.204 ;
     RECT  22.302 30.179 22.356 30.204 ;
     RECT  22.374 30.179 22.428 30.204 ;
     RECT  22.446 30.179 22.5 30.204 ;
     RECT  22.518 30.179 22.572 30.204 ;
     RECT  22.59 30.179 22.644 30.204 ;
     RECT  22.662 30.179 22.716 30.204 ;
     RECT  22.734 30.179 22.788 30.204 ;
     RECT  22.806 30.179 22.86 30.204 ;
     RECT  22.878 30.179 22.932 30.204 ;
     RECT  22.95 30.179 23.004 30.204 ;
     RECT  23.022 30.179 23.076 30.204 ;
     RECT  23.094 30.179 23.148 30.204 ;
     RECT  23.166 30.179 23.22 30.204 ;
     RECT  23.238 30.179 23.292 30.204 ;
     RECT  23.31 30.179 23.364 30.204 ;
     RECT  23.382 30.179 23.436 30.204 ;
     RECT  23.454 30.179 23.508 30.204 ;
     RECT  23.526 30.179 23.58 30.204 ;
     RECT  23.598 30.179 23.652 30.204 ;
     RECT  23.67 30.179 23.724 30.204 ;
     RECT  23.742 30.179 23.796 30.204 ;
     RECT  23.814 30.179 23.868 30.204 ;
     RECT  26.244 30.037 28.494 30.179 ;
     RECT  26.262 30.179 26.316 30.204 ;
     RECT  26.334 30.179 26.388 30.204 ;
     RECT  26.406 30.179 26.46 30.204 ;
     RECT  26.478 30.179 26.532 30.204 ;
     RECT  26.55 30.179 26.604 30.204 ;
     RECT  26.622 30.179 26.676 30.204 ;
     RECT  26.694 30.179 26.748 30.204 ;
     RECT  26.766 30.179 26.82 30.204 ;
     RECT  26.838 30.179 26.892 30.204 ;
     RECT  26.91 30.179 26.964 30.204 ;
     RECT  26.982 30.179 27.036 30.204 ;
     RECT  27.054 30.179 27.108 30.204 ;
     RECT  27.126 30.179 27.18 30.204 ;
     RECT  27.198 30.179 27.252 30.204 ;
     RECT  27.27 30.179 27.324 30.204 ;
     RECT  27.342 30.179 27.396 30.204 ;
     RECT  27.414 30.179 27.468 30.204 ;
     RECT  27.486 30.179 27.54 30.204 ;
     RECT  27.558 30.179 27.612 30.204 ;
     RECT  27.63 30.179 27.684 30.204 ;
     RECT  27.702 30.179 27.756 30.204 ;
     RECT  27.774 30.179 27.828 30.204 ;
     RECT  27.846 30.179 27.9 30.204 ;
     RECT  27.918 30.179 27.972 30.204 ;
     RECT  27.99 30.179 28.044 30.204 ;
     RECT  28.062 30.179 28.116 30.204 ;
     RECT  28.134 30.179 28.188 30.204 ;
     RECT  28.206 30.179 28.26 30.204 ;
     RECT  28.278 30.179 28.332 30.204 ;
     RECT  28.35 30.179 28.404 30.204 ;
     RECT  28.422 30.179 28.476 30.204 ;
     RECT  40.644 30.173 45.198 30.179 ;
     RECT  40.662 30.179 40.716 30.204 ;
     RECT  40.734 30.179 40.788 30.204 ;
     RECT  40.806 30.179 40.86 30.204 ;
     RECT  40.878 30.179 40.932 30.204 ;
     RECT  40.95 30.179 41.004 30.204 ;
     RECT  41.022 30.179 41.076 30.204 ;
     RECT  41.094 30.179 41.148 30.204 ;
     RECT  41.166 30.179 41.22 30.204 ;
     RECT  41.238 30.179 41.292 30.204 ;
     RECT  41.31 30.179 41.364 30.204 ;
     RECT  41.382 30.179 41.436 30.204 ;
     RECT  41.454 30.179 41.508 30.204 ;
     RECT  41.526 30.179 41.58 30.204 ;
     RECT  41.598 30.179 41.652 30.204 ;
     RECT  41.67 30.179 41.724 30.204 ;
     RECT  41.742 30.179 41.796 30.204 ;
     RECT  41.814 30.179 41.868 30.204 ;
     RECT  41.886 30.179 41.94 30.204 ;
     RECT  41.958 30.179 42.012 30.204 ;
     RECT  42.03 30.179 42.084 30.204 ;
     RECT  42.102 30.179 42.156 30.204 ;
     RECT  42.174 30.179 42.228 30.204 ;
     RECT  42.246 30.179 42.3 30.204 ;
     RECT  42.318 30.179 42.372 30.204 ;
     RECT  42.39 30.179 42.444 30.204 ;
     RECT  42.462 30.179 42.516 30.204 ;
     RECT  42.534 30.179 42.588 30.204 ;
     RECT  42.606 30.179 42.66 30.204 ;
     RECT  42.678 30.179 42.732 30.204 ;
     RECT  42.75 30.179 42.804 30.204 ;
     RECT  42.822 30.179 42.876 30.204 ;
     RECT  42.894 30.179 42.948 30.204 ;
     RECT  42.966 30.179 43.02 30.204 ;
     RECT  43.038 30.179 43.092 30.204 ;
     RECT  43.11 30.179 43.164 30.204 ;
     RECT  43.182 30.179 43.236 30.204 ;
     RECT  43.254 30.179 43.308 30.204 ;
     RECT  43.326 30.179 43.38 30.204 ;
     RECT  43.398 30.179 43.452 30.204 ;
     RECT  43.47 30.179 43.524 30.204 ;
     RECT  43.542 30.179 43.596 30.204 ;
     RECT  43.614 30.179 43.668 30.204 ;
     RECT  43.686 30.179 43.74 30.204 ;
     RECT  43.758 30.179 43.812 30.204 ;
     RECT  43.83 30.179 43.884 30.204 ;
     RECT  43.902 30.179 43.956 30.204 ;
     RECT  43.974 30.179 44.028 30.204 ;
     RECT  44.046 30.179 44.1 30.204 ;
     RECT  44.118 30.179 44.172 30.204 ;
     RECT  44.19 30.179 44.244 30.204 ;
     RECT  44.262 30.179 44.316 30.204 ;
     RECT  44.334 30.179 44.388 30.204 ;
     RECT  44.406 30.179 44.46 30.204 ;
     RECT  44.478 30.179 44.532 30.204 ;
     RECT  44.55 30.179 44.604 30.204 ;
     RECT  44.622 30.179 44.676 30.204 ;
     RECT  44.694 30.179 44.748 30.204 ;
     RECT  44.766 30.179 44.82 30.204 ;
     RECT  44.838 30.179 44.892 30.204 ;
     RECT  44.91 30.179 44.964 30.204 ;
     RECT  44.982 30.179 45.036 30.204 ;
     RECT  45.054 30.179 45.108 30.204 ;
     RECT  45.126 30.179 45.18 30.204 ;
    LAYER M4 ;
     RECT  0.084 9.36 0.227 9.384 ;
     RECT  0.06 9.384 0.227 9.456 ;
     RECT  0.084 9.456 0.227 9.48 ;
     RECT  0.06 9.48 0.227 9.552 ;
     RECT  0.084 9.552 0.227 9.576 ;
     RECT  0.06 9.576 0.227 9.648 ;
     RECT  0.084 9.648 0.227 9.672 ;
     RECT  0.06 9.672 0.227 9.744 ;
     RECT  0.084 9.744 0.227 9.768 ;
     RECT  0.06 9.768 0.227 9.84 ;
     RECT  0.084 9.84 0.227 9.864 ;
     RECT  0.06 9.864 0.227 9.936 ;
     RECT  0.084 9.936 0.227 9.96 ;
     RECT  0.06 9.96 0.227 10.032 ;
     RECT  0.084 10.032 0.227 10.056 ;
     RECT  0.06 10.056 0.227 10.128 ;
     RECT  0.084 10.128 0.227 10.152 ;
     RECT  0.06 10.152 0.227 10.224 ;
     RECT  0.084 10.224 0.227 10.248 ;
     RECT  0.181 18.816 0.325 18.84 ;
     RECT  0.227 9.456 0.371 10.248 ;
     RECT  0.371 9.552 2.408 10.248 ;
     RECT  0.325 18.816 2.408 19.032 ;
     RECT  2.408 2.148 2.512 27.552 ;
     RECT  2.512 2.418 2.6 27.552 ;
     RECT  2.6 2.418 2.704 27.822 ;
     RECT  2.704 9.888 4.237 9.912 ;
     RECT  4.237 9.888 4.501 10.248 ;
     RECT  4.501 9.888 5.108 11.016 ;
     RECT  2.704 18.816 5.108 19.032 ;
     RECT  5.108 2.148 5.212 27.552 ;
     RECT  5.212 2.418 5.3 27.552 ;
     RECT  5.3 2.418 5.404 27.822 ;
     RECT  5.404 9.888 7.808 9.912 ;
     RECT  5.404 10.992 7.808 11.016 ;
     RECT  5.404 18.816 7.808 19.032 ;
     RECT  7.808 2.148 7.912 27.552 ;
     RECT  7.912 2.418 8 27.552 ;
     RECT  8 2.418 8.104 27.822 ;
     RECT  8.104 23.232 9.097 23.256 ;
     RECT  8.104 24.24 9.097 24.264 ;
     RECT  8.104 26.208 9.133 26.232 ;
     RECT  9.133 25.632 9.173 26.232 ;
     RECT  9.253 22.176 9.34 22.2 ;
     RECT  9.173 25.632 9.565 25.704 ;
     RECT  9.097 23.232 10.069 24.264 ;
     RECT  8.104 9.888 10.105 9.912 ;
     RECT  8.104 10.992 10.105 11.016 ;
     RECT  10.105 9.888 10.508 11.016 ;
     RECT  8.104 18.816 10.508 19.032 ;
     RECT  10.069 22.656 10.508 24.264 ;
     RECT  9.565 25.488 10.508 25.704 ;
     RECT  10.508 2.148 10.612 27.552 ;
     RECT  10.612 2.418 10.7 27.552 ;
     RECT  10.7 2.418 10.804 27.822 ;
     RECT  10.804 12.48 10.865 12.552 ;
     RECT  10.804 10.368 11.081 11.016 ;
     RECT  10.804 21.648 11.459 25.512 ;
     RECT  10.804 26.592 11.585 26.856 ;
     RECT  11.459 22.56 11.729 25.512 ;
     RECT  10.804 18.816 11.869 19.992 ;
     RECT  11.729 22.704 11.893 25.512 ;
     RECT  11.585 26.592 11.893 26.616 ;
     RECT  10.804 14.64 11.9 14.904 ;
     RECT  11.9 14.64 11.987 15.528 ;
     RECT  11.081 10.368 12.017 10.584 ;
     RECT  11.893 22.704 12.028 26.616 ;
     RECT  10.804 13.584 12.044 13.608 ;
     RECT  12.044 13.584 12.053 13.656 ;
     RECT  12.028 22.704 12.053 23.304 ;
     RECT  10.865 12.48 12.131 12.504 ;
     RECT  12.053 13.632 12.131 13.656 ;
     RECT  12.028 24.72 12.589 26.616 ;
     RECT  11.941 16.56 12.697 16.584 ;
     RECT  11.869 18.624 13.055 19.992 ;
     RECT  12.017 10.368 13.208 10.392 ;
     RECT  13.201 13.632 13.208 13.656 ;
     RECT  11.987 14.64 13.208 15.336 ;
     RECT  12.697 16.56 13.208 17.112 ;
     RECT  13.055 18.192 13.208 19.992 ;
     RECT  13.201 21.696 13.208 21.72 ;
     RECT  12.053 22.8 13.208 23.304 ;
     RECT  12.589 24.72 13.208 26.664 ;
     RECT  13.208 2.148 13.312 27.552 ;
     RECT  13.312 2.418 13.4 27.552 ;
     RECT  13.4 2.418 13.504 27.822 ;
     RECT  13.504 21.072 13.709 27.384 ;
     RECT  13.709 24.144 13.925 27.048 ;
     RECT  13.504 16.512 14.243 19.032 ;
     RECT  13.504 14.736 14.249 14.904 ;
     RECT  14.243 16.512 14.249 17.064 ;
     RECT  13.504 10.368 14.321 10.632 ;
     RECT  13.925 24.144 14.429 25.272 ;
     RECT  13.709 21.072 14.501 23.064 ;
     RECT  14.249 14.88 14.533 14.904 ;
     RECT  13.925 26.352 14.537 27.048 ;
     RECT  14.533 14.88 14.573 15.432 ;
     RECT  14.501 21.072 14.605 21.96 ;
     RECT  14.605 20.688 14.677 21.96 ;
     RECT  14.249 17.04 14.681 17.064 ;
     RECT  14.573 15.408 14.713 15.432 ;
     RECT  14.243 18.432 14.713 19.032 ;
     RECT  14.677 20.112 14.713 21.96 ;
     RECT  14.429 24.144 14.753 24.744 ;
     RECT  14.537 26.64 14.785 27.048 ;
     RECT  13.504 13.632 14.825 13.656 ;
     RECT  14.321 10.608 15.037 10.632 ;
     RECT  13.504 12 15.037 12.36 ;
     RECT  15.037 10.608 15.325 12.36 ;
     RECT  15.325 10.608 15.908 13.272 ;
     RECT  14.713 15.408 15.908 16.056 ;
     RECT  14.713 18.432 15.908 21.96 ;
     RECT  15.109 23.376 15.908 23.4 ;
     RECT  14.753 24.432 15.908 24.744 ;
     RECT  14.785 26.64 15.908 27.336 ;
     RECT  15.908 2.148 16.012 27.552 ;
     RECT  16.012 2.418 16.1 27.552 ;
     RECT  16.1 2.418 16.204 27.822 ;
     RECT  16.204 12 16.373 12.84 ;
     RECT  16.204 18.816 16.589 27.192 ;
     RECT  16.373 12.048 16.733 12.84 ;
     RECT  16.589 20.064 17.021 27.192 ;
     RECT  16.733 12.48 17.129 12.84 ;
     RECT  17.021 20.064 17.129 26.952 ;
     RECT  17.129 12.48 17.165 12.6 ;
     RECT  16.204 17.088 17.171 17.208 ;
     RECT  16.204 10.608 17.507 10.632 ;
     RECT  17.129 20.064 17.561 25.656 ;
     RECT  16.589 18.816 17.881 19.032 ;
     RECT  17.561 20.064 17.881 20.088 ;
     RECT  16.204 15.888 18.205 16.056 ;
     RECT  17.171 17.184 18.205 17.208 ;
     RECT  18.205 15.888 18.229 17.208 ;
     RECT  17.881 18.816 18.229 20.088 ;
     RECT  17.165 12.576 18.608 12.6 ;
     RECT  17.233 13.632 18.608 13.656 ;
     RECT  18.229 15.888 18.608 20.088 ;
     RECT  17.561 21.072 18.608 25.656 ;
     RECT  17.129 26.784 18.608 26.952 ;
     RECT  18.608 2.148 18.712 27.552 ;
     RECT  18.712 2.418 18.8 27.552 ;
     RECT  18.8 2.418 18.904 27.822 ;
     RECT  18.904 26.88 18.929 26.904 ;
     RECT  18.904 18.816 19.516 25.32 ;
     RECT  18.904 12.576 19.721 13.56 ;
     RECT  18.904 16.08 19.897 16.584 ;
     RECT  18.904 17.616 19.969 17.64 ;
     RECT  19.721 13.536 20.005 13.56 ;
     RECT  19.516 18.816 20.14 21.768 ;
     RECT  19.897 15.12 20.533 16.584 ;
     RECT  19.516 22.752 20.617 25.32 ;
     RECT  20.365 26.352 20.617 26.376 ;
     RECT  20.533 15.072 20.689 16.584 ;
     RECT  19.969 17.616 20.689 17.688 ;
     RECT  20.14 20.88 20.689 21.768 ;
     RECT  20.617 22.752 20.689 26.376 ;
     RECT  20.689 20.88 20.941 26.376 ;
     RECT  20.905 12 21.013 12.024 ;
     RECT  21.013 12 21.085 12.504 ;
     RECT  21.085 12 21.121 12.552 ;
     RECT  20.14 18.816 21.149 19.8 ;
     RECT  20.941 20.88 21.149 26.808 ;
     RECT  20.833 10.08 21.308 10.104 ;
     RECT  21.121 11.76 21.308 12.552 ;
     RECT  20.005 13.536 21.308 14.04 ;
     RECT  20.689 15.072 21.308 17.688 ;
     RECT  21.149 18.816 21.308 26.808 ;
     RECT  21.308 2.148 21.412 27.552 ;
     RECT  21.412 2.418 21.5 27.552 ;
     RECT  21.5 2.418 21.604 27.822 ;
     RECT  21.604 16.08 22.061 17.16 ;
     RECT  22.061 17.136 22.133 17.16 ;
     RECT  22.373 29.664 22.457 29.688 ;
     RECT  21.604 10.08 22.529 10.296 ;
     RECT  21.604 18.816 22.547 19.8 ;
     RECT  21.604 11.664 22.709 12.552 ;
     RECT  21.604 14.16 22.741 14.232 ;
     RECT  21.604 21.696 22.777 27.384 ;
     RECT  22.061 16.08 22.921 16.104 ;
     RECT  22.777 20.976 23.005 27.384 ;
     RECT  22.529 10.272 23.281 10.296 ;
     RECT  22.709 11.664 23.281 12.072 ;
     RECT  22.741 14.16 23.281 14.52 ;
     RECT  23.281 13.92 23.461 14.52 ;
     RECT  23.18 30.144 23.795 30.168 ;
     RECT  23.353 9.072 23.797 9.096 ;
     RECT  23.281 10.272 23.797 12.072 ;
     RECT  23.797 9.072 23.845 12.072 ;
     RECT  23.461 13.68 23.845 14.52 ;
     RECT  22.921 15.984 23.857 16.104 ;
     RECT  22.885 17.616 23.857 17.64 ;
     RECT  23.209 20.64 23.893 20.664 ;
     RECT  23.845 9.072 24.008 14.52 ;
     RECT  23.857 15.984 24.008 17.64 ;
     RECT  22.547 18.816 24.008 19.32 ;
     RECT  23.893 20.592 24.008 20.664 ;
     RECT  23.005 21.696 24.008 27.384 ;
     RECT  24.008 2.148 24.112 27.552 ;
     RECT  24.112 2.418 24.2 27.552 ;
     RECT  24.2 2.418 24.304 27.822 ;
     RECT  24.304 13.104 24.419 14.952 ;
     RECT  24.304 20.592 24.419 27.432 ;
     RECT  24.304 15.984 24.509 19.32 ;
     RECT  24.419 13.104 24.617 14.808 ;
     RECT  24.304 9.264 24.761 9.288 ;
     RECT  24.419 20.592 24.905 26.808 ;
     RECT  24.509 15.984 25.121 17.4 ;
     RECT  24.304 10.8 25.513 12.072 ;
     RECT  25.513 10.272 25.549 12.072 ;
     RECT  24.617 13.872 25.585 14.808 ;
     RECT  25.121 15.984 25.585 16.104 ;
     RECT  25.549 10.272 25.657 12.504 ;
     RECT  25.585 13.872 25.657 16.104 ;
     RECT  24.509 18.528 25.669 19.32 ;
     RECT  24.905 20.592 25.669 26.664 ;
     RECT  25.657 13.632 25.715 16.104 ;
     RECT  25.121 17.328 26.017 17.4 ;
     RECT  25.669 18.528 26.017 26.664 ;
     RECT  25.657 9.552 26.053 12.504 ;
     RECT  26.017 17.328 26.089 26.664 ;
     RECT  26.053 9.552 26.161 12.552 ;
     RECT  25.715 13.632 26.161 15.384 ;
     RECT  26.161 9.552 26.708 15.384 ;
     RECT  26.089 16.512 26.708 27.384 ;
     RECT  26.708 2.148 26.809 27.552 ;
     RECT  26.809 2.148 26.812 27.624 ;
     RECT  26.812 2.418 26.9 27.624 ;
     RECT  26.9 2.418 27.004 27.822 ;
     RECT  27.004 21.312 27.155 27.624 ;
     RECT  27.004 8.496 27.299 8.52 ;
     RECT  27.004 9.6 27.34 11.976 ;
     RECT  27.004 13.056 27.34 14.52 ;
     RECT  27.34 10.704 27.965 11.976 ;
     RECT  27.004 18.528 28.045 19.944 ;
     RECT  27.155 21.648 28.145 27.624 ;
     RECT  27.34 9.6 28.181 9.624 ;
     RECT  27.34 13.104 28.397 14.52 ;
     RECT  28.397 13.2 28.429 14.52 ;
     RECT  28.429 13.2 28.433 15.192 ;
     RECT  26.3 30.144 28.433 30.168 ;
     RECT  28.433 13.344 28.825 15.192 ;
     RECT  28.285 16.272 28.825 16.968 ;
     RECT  27.965 10.992 28.933 11.976 ;
     RECT  28.933 10.848 29.041 11.976 ;
     RECT  28.145 21.648 29.293 27.384 ;
     RECT  29.041 10.08 29.408 11.976 ;
     RECT  28.825 13.344 29.408 16.968 ;
     RECT  28.045 18.528 29.408 19.848 ;
     RECT  29.293 21.12 29.408 27.384 ;
     RECT  29.408 2.148 29.512 27.552 ;
     RECT  29.512 2.418 29.6 27.552 ;
     RECT  29.6 2.418 29.704 27.822 ;
     RECT  29.704 9.36 30.305 12.504 ;
     RECT  29.704 13.632 30.449 15.048 ;
     RECT  30.449 14.112 30.629 15.048 ;
     RECT  29.704 16.176 30.697 16.2 ;
     RECT  29.704 21.12 30.755 27.384 ;
     RECT  30.305 9.36 30.773 9.528 ;
     RECT  30.755 21.696 30.809 27.384 ;
     RECT  29.704 18.768 31.093 20.088 ;
     RECT  30.697 15.984 31.381 16.2 ;
     RECT  29.704 17.424 31.381 17.448 ;
     RECT  31.093 18.768 31.417 20.616 ;
     RECT  31.417 18.528 31.453 20.616 ;
     RECT  30.305 10.848 31.525 12.504 ;
     RECT  30.629 14.112 31.525 14.52 ;
     RECT  31.525 10.848 31.813 12.792 ;
     RECT  31.525 13.824 31.813 14.52 ;
     RECT  30.773 9.504 31.885 9.528 ;
     RECT  31.813 10.848 31.885 14.52 ;
     RECT  31.381 15.984 31.921 17.448 ;
     RECT  31.453 18.432 31.921 20.616 ;
     RECT  31.885 9.504 32.108 14.52 ;
     RECT  31.921 15.984 32.108 20.616 ;
     RECT  30.809 21.696 32.108 26.904 ;
     RECT  32.108 2.148 32.212 27.552 ;
     RECT  32.212 2.418 32.3 27.552 ;
     RECT  32.3 2.418 32.404 27.822 ;
     RECT  32.404 10.416 32.429 14.904 ;
     RECT  32.429 10.992 32.579 14.904 ;
     RECT  32.404 15.984 32.579 17.112 ;
     RECT  32.579 13.584 32.753 14.712 ;
     RECT  32.404 9.264 32.861 9.288 ;
     RECT  32.579 16.032 33.005 17.112 ;
     RECT  32.404 18.432 33.185 25.512 ;
     RECT  33.185 18.432 33.299 20.568 ;
     RECT  33.299 18.432 33.34 20.04 ;
     RECT  32.579 10.992 33.397 12.504 ;
     RECT  33.397 10.224 33.484 12.504 ;
     RECT  33.185 21.792 33.493 25.512 ;
     RECT  32.753 13.632 33.545 14.712 ;
     RECT  33.005 16.704 33.577 17.112 ;
     RECT  33.34 18.432 33.577 19.032 ;
     RECT  33.545 14.208 33.613 14.712 ;
     RECT  33.484 10.416 34.117 12.504 ;
     RECT  33.613 14.208 34.729 15.432 ;
     RECT  33.577 16.704 34.729 19.032 ;
     RECT  34.117 10.416 34.808 12.936 ;
     RECT  34.729 14.208 34.808 19.032 ;
     RECT  33.34 20.016 34.808 20.04 ;
     RECT  33.493 21.792 34.808 25.608 ;
     RECT  32.404 26.592 34.808 26.808 ;
     RECT  34.808 2.148 34.912 27.552 ;
     RECT  34.912 2.418 35 27.552 ;
     RECT  35 2.418 35.104 27.822 ;
     RECT  35.104 17.808 35.129 19.512 ;
     RECT  35.104 16.08 35.381 16.536 ;
     RECT  35.104 9.072 35.603 9.528 ;
     RECT  35.104 10.8 35.705 14.904 ;
     RECT  35.705 10.8 35.849 14.712 ;
     RECT  35.104 21.072 36.029 26.808 ;
     RECT  35.603 9.408 36.065 9.528 ;
     RECT  35.849 11.088 36.137 14.52 ;
     RECT  35.129 17.808 36.181 18.792 ;
     RECT  36.065 9.504 36.245 9.528 ;
     RECT  36.137 11.136 36.245 14.52 ;
     RECT  36.181 17.808 36.268 19.368 ;
     RECT  36.029 21.072 36.353 26.616 ;
     RECT  36.268 17.808 36.497 18.888 ;
     RECT  36.353 21.072 36.565 25.512 ;
     RECT  35.381 16.512 36.709 16.536 ;
     RECT  36.709 16.08 36.889 16.536 ;
     RECT  36.565 20.64 37.285 25.512 ;
     RECT  36.245 11.136 37.508 14.424 ;
     RECT  36.889 15.552 37.508 16.536 ;
     RECT  36.497 17.808 37.508 18.792 ;
     RECT  37.285 20.064 37.508 25.512 ;
     RECT  36.353 26.592 37.508 26.616 ;
     RECT  37.508 2.148 37.612 27.552 ;
     RECT  37.612 2.418 37.7 27.552 ;
     RECT  37.7 2.418 37.804 27.822 ;
     RECT  37.804 19.728 38.333 25.608 ;
     RECT  38.333 19.728 38.771 19.944 ;
     RECT  37.804 10.416 38.867 18.504 ;
     RECT  38.867 10.416 38.977 16.44 ;
     RECT  38.771 19.728 39.013 19.848 ;
     RECT  38.977 9.888 39.085 16.44 ;
     RECT  38.333 20.928 39.625 25.608 ;
     RECT  37.804 26.592 39.625 26.616 ;
     RECT  39.625 20.928 39.769 27.144 ;
     RECT  39.085 9.6 40.208 16.44 ;
     RECT  38.867 17.616 40.208 18.504 ;
     RECT  39.013 19.536 40.208 19.848 ;
     RECT  39.769 20.88 40.208 27.144 ;
     RECT  40.208 2.148 40.312 27.552 ;
     RECT  40.312 2.418 40.4 27.552 ;
     RECT  40.4 2.418 40.504 27.822 ;
     RECT  40.504 18.192 40.601 27.72 ;
     RECT  39.913 28.992 40.705 29.016 ;
     RECT  40.504 9.072 41.105 17.016 ;
     RECT  40.705 28.992 41.825 29.064 ;
     RECT  41.105 16.08 42.037 17.016 ;
     RECT  40.601 18.192 42.037 20.616 ;
     RECT  41.105 9.072 42.109 14.808 ;
     RECT  42.037 16.08 42.109 20.616 ;
     RECT  40.601 21.792 42.109 27.72 ;
     RECT  40.165 30.144 42.113 30.168 ;
     RECT  42.109 16.08 42.145 27.72 ;
     RECT  41.825 28.992 42.401 29.016 ;
     RECT  42.109 8.688 42.749 14.808 ;
     RECT  42.145 15.936 42.749 27.72 ;
     RECT  42.757 7.296 42.908 7.32 ;
     RECT  42.749 8.688 42.908 27.72 ;
     RECT  42.908 2.148 43.012 27.72 ;
     RECT  43.012 2.418 43.1 27.72 ;
     RECT  43.1 2.418 43.204 27.822 ;
     RECT  43.204 18.48 43.445 27.672 ;
     RECT  43.445 18.48 43.517 27.624 ;
     RECT  43.204 8.976 43.589 14.664 ;
     RECT  43.517 18.48 43.589 19.848 ;
     RECT  43.189 30.144 44.309 30.168 ;
     RECT  43.517 21.168 44.629 27.624 ;
     RECT  43.589 18.48 44.725 19.656 ;
     RECT  44.809 29.04 44.993 29.064 ;
     RECT  44.725 18.48 45.025 20.04 ;
     RECT  44.629 21.168 45.025 27.672 ;
     RECT  43.589 9.36 45.241 14.376 ;
     RECT  45.241 9.36 45.608 14.952 ;
     RECT  43.204 16.08 45.608 17.208 ;
     RECT  45.025 18.48 45.608 27.672 ;
     RECT  45.608 2.148 45.712 27.672 ;
     RECT  45.712 2.418 45.8 27.672 ;
     RECT  45.8 2.418 45.904 27.822 ;
     RECT  45.904 20.64 46.001 27.672 ;
     RECT  45.904 9.12 46.019 13.704 ;
     RECT  45.904 19.536 46.067 19.56 ;
     RECT  45.904 18.144 46.108 18.408 ;
     RECT  46.108 18.144 46.145 18.168 ;
     RECT  45.904 14.832 46.253 17.16 ;
     RECT  46.001 20.64 46.505 27.384 ;
     RECT  46.505 20.64 46.577 26.904 ;
     RECT  46.577 20.64 47.045 26.808 ;
     RECT  47.045 20.64 47.117 26.568 ;
     RECT  46.253 14.832 47.225 16.824 ;
     RECT  47.117 20.64 47.225 26.424 ;
     RECT  47.225 20.64 47.761 24.6 ;
     RECT  47.761 20.112 47.797 24.6 ;
     RECT  47.225 15.216 47.833 16.824 ;
     RECT  47.797 19.536 48.193 24.6 ;
     RECT  46.019 9.36 48.308 13.704 ;
     RECT  47.833 15.216 48.308 17.496 ;
     RECT  48.193 19.344 48.308 24.6 ;
     RECT  47.225 25.776 48.308 26.424 ;
     RECT  48.308 2.148 48.412 27.552 ;
     RECT  48.412 2.418 48.5 27.552 ;
     RECT  48.5 2.418 48.604 27.822 ;
     RECT  48.604 26.016 50.605 26.088 ;
     RECT  50.605 26.016 50.821 26.664 ;
     RECT  48.604 9.456 51.008 24.504 ;
     RECT  50.821 25.488 51.008 26.808 ;
     RECT  51.008 2.148 51.112 27.552 ;
     RECT  51.112 2.418 51.2 27.552 ;
     RECT  51.2 2.418 51.304 27.822 ;
     RECT  51.304 15.936 51.473 26.808 ;
     RECT  51.304 9.504 51.833 13.704 ;
     RECT  51.473 19.824 52.333 26.808 ;
     RECT  51.833 10.32 52.369 13.704 ;
     RECT  52.369 10.32 52.405 14.52 ;
     RECT  51.473 15.936 52.481 18.504 ;
     RECT  52.405 10.32 52.657 14.616 ;
     RECT  52.481 18.192 52.765 18.504 ;
     RECT  52.333 19.824 52.765 27.336 ;
     RECT  52.657 10.32 53.708 14.808 ;
     RECT  52.481 15.936 53.708 17.16 ;
     RECT  52.765 18.192 53.708 27.336 ;
     RECT  53.708 2.148 53.812 27.552 ;
     RECT  53.812 2.418 53.9 27.552 ;
     RECT  53.9 2.418 54.004 27.822 ;
     RECT  54.004 13.632 54.131 26.904 ;
     RECT  54.131 13.632 54.137 18.84 ;
     RECT  54.137 13.632 54.173 18.504 ;
     RECT  54.131 19.824 54.173 26.904 ;
     RECT  54.173 20.064 54.569 26.904 ;
     RECT  54.173 14.208 54.707 18.504 ;
     RECT  54.707 14.784 54.785 18.504 ;
     RECT  54.569 20.112 55.001 26.904 ;
     RECT  54.004 10.32 55.033 12.36 ;
     RECT  54.785 14.784 55.145 14.808 ;
     RECT  55.001 20.112 55.361 26.808 ;
     RECT  55.361 20.112 55.433 26.76 ;
     RECT  55.433 20.112 56.015 26.376 ;
     RECT  54.785 16.08 56.053 18.504 ;
     RECT  56.053 16.08 56.221 18.744 ;
     RECT  55.033 9.504 56.408 12.36 ;
     RECT  56.221 16.08 56.408 19.032 ;
     RECT  56.015 20.064 56.408 26.376 ;
     RECT  56.408 2.148 56.512 27.552 ;
     RECT  56.512 2.418 56.6 27.552 ;
     RECT  56.6 2.418 56.704 27.822 ;
     RECT  56.704 18.192 56.765 19.032 ;
     RECT  56.704 9.648 56.945 12.84 ;
     RECT  56.704 20.064 57.089 26.376 ;
     RECT  56.765 18.48 57.629 19.032 ;
     RECT  57.629 19.008 58.021 19.032 ;
     RECT  57.089 20.064 58.021 26.328 ;
     RECT  58.021 19.008 58.237 26.328 ;
     RECT  56.945 10.32 58.625 12.84 ;
     RECT  58.645 8.448 58.669 8.472 ;
     RECT  58.625 9.696 58.669 12.84 ;
     RECT  58.129 7.344 59.108 7.368 ;
     RECT  58.669 8.448 59.108 12.84 ;
     RECT  56.704 16.08 59.108 16.104 ;
     RECT  58.237 19.008 59.108 26.904 ;
     RECT  59.108 2.148 59.212 27.552 ;
     RECT  59.212 2.418 59.3 27.552 ;
     RECT  59.3 2.418 59.404 27.822 ;
     RECT  59.404 20.064 59.609 26.904 ;
     RECT  59.404 7.104 60.005 12.84 ;
     RECT  59.609 20.064 60.113 26.328 ;
     RECT  59.404 16.08 60.653 16.104 ;
     RECT  60.113 20.064 60.761 26.088 ;
     RECT  60.973 18.768 61.148 18.792 ;
     RECT  61.148 18.576 61.189 18.792 ;
     RECT  60.761 20.064 61.189 25.848 ;
     RECT  61.189 18.576 61.369 25.848 ;
     RECT  60.005 7.104 61.669 9.288 ;
     RECT  60.005 10.32 61.669 12.84 ;
     RECT  61.669 7.104 61.808 12.84 ;
     RECT  61.369 18.144 61.808 25.848 ;
     RECT  61.808 2.148 61.912 27.552 ;
     RECT  61.912 2.418 62 27.552 ;
     RECT  62 2.418 62.104 27.822 ;
     RECT  62.104 19.344 62.309 25.992 ;
     RECT  62.104 7.104 62.381 12.84 ;
     RECT  62.381 7.296 62.483 12.84 ;
     RECT  62.483 7.392 62.675 12.84 ;
     RECT  62.675 7.584 62.741 12.84 ;
     RECT  62.309 20.112 63.457 25.992 ;
     RECT  62.741 7.632 63.781 12.84 ;
     RECT  63.781 7.152 63.817 12.84 ;
     RECT  63.817 7.056 63.853 12.84 ;
     RECT  63.457 20.016 63.853 25.992 ;
     RECT  63.853 6.864 64.692 6.888 ;
     RECT  63.853 6.888 64.716 6.96 ;
     RECT  63.853 6.96 64.692 6.984 ;
     RECT  63.853 6.984 64.716 7.056 ;
     RECT  63.853 7.056 64.692 7.08 ;
     RECT  63.853 7.08 64.716 7.152 ;
     RECT  63.853 7.152 64.692 7.176 ;
     RECT  63.853 7.176 64.716 7.248 ;
     RECT  63.853 7.248 64.692 7.272 ;
     RECT  63.853 7.272 64.716 7.344 ;
     RECT  63.853 7.344 64.692 7.368 ;
     RECT  63.853 7.368 64.716 7.44 ;
     RECT  63.853 7.44 64.692 7.464 ;
     RECT  63.853 7.464 64.716 7.536 ;
     RECT  63.853 7.536 64.692 7.56 ;
     RECT  63.853 7.56 64.716 7.632 ;
     RECT  63.853 7.632 64.692 7.656 ;
     RECT  63.853 7.656 64.716 7.728 ;
     RECT  63.853 7.728 64.692 7.752 ;
     RECT  63.853 7.752 64.716 7.824 ;
     RECT  63.853 7.824 64.692 7.848 ;
     RECT  63.853 7.848 64.716 7.92 ;
     RECT  63.853 7.92 64.692 7.944 ;
     RECT  63.853 7.944 64.716 8.016 ;
     RECT  63.853 8.016 64.692 8.04 ;
     RECT  63.853 8.04 64.716 8.112 ;
     RECT  63.853 8.112 64.692 8.136 ;
     RECT  63.853 8.136 64.716 8.208 ;
     RECT  63.853 8.208 64.692 8.232 ;
     RECT  63.853 8.232 64.716 8.304 ;
     RECT  63.853 8.304 64.692 8.328 ;
     RECT  63.853 8.328 64.716 8.4 ;
     RECT  63.853 8.4 64.692 8.424 ;
     RECT  63.853 8.424 64.716 8.496 ;
     RECT  63.853 8.496 64.692 8.52 ;
     RECT  63.853 8.52 64.716 8.592 ;
     RECT  63.853 8.592 64.692 8.616 ;
     RECT  63.853 8.616 64.716 8.688 ;
     RECT  63.853 8.688 64.692 8.712 ;
     RECT  63.853 8.712 64.716 8.784 ;
     RECT  63.853 8.784 64.692 8.808 ;
     RECT  63.853 8.808 64.716 8.88 ;
     RECT  63.853 8.88 64.692 8.904 ;
     RECT  63.853 8.904 64.716 8.976 ;
     RECT  63.853 8.976 64.692 9 ;
     RECT  63.853 9 64.716 9.072 ;
     RECT  63.853 9.072 64.692 9.096 ;
     RECT  63.853 9.096 64.716 9.168 ;
     RECT  63.853 9.168 64.692 9.192 ;
     RECT  63.853 9.192 64.716 9.264 ;
     RECT  63.853 9.264 64.692 9.288 ;
     RECT  63.853 9.288 64.716 9.36 ;
     RECT  63.853 9.36 64.692 9.384 ;
     RECT  63.853 9.384 64.716 9.456 ;
     RECT  63.853 9.456 64.692 9.48 ;
     RECT  63.853 9.48 64.716 9.552 ;
     RECT  63.853 9.552 64.692 9.576 ;
     RECT  63.853 9.576 64.716 9.648 ;
     RECT  63.853 9.648 64.692 9.672 ;
     RECT  63.853 9.672 64.716 9.744 ;
     RECT  63.853 9.744 64.692 9.768 ;
     RECT  63.853 9.768 64.716 9.84 ;
     RECT  63.853 9.84 64.692 9.864 ;
     RECT  63.853 9.864 64.716 9.936 ;
     RECT  63.853 9.936 64.692 9.96 ;
     RECT  63.853 9.96 64.716 10.032 ;
     RECT  63.853 10.032 64.692 10.056 ;
     RECT  63.853 10.056 64.716 10.128 ;
     RECT  63.853 10.128 64.692 10.152 ;
     RECT  63.853 10.152 64.716 10.224 ;
     RECT  63.853 10.224 64.692 10.248 ;
     RECT  63.853 10.248 64.716 10.32 ;
     RECT  63.853 10.32 64.692 10.344 ;
     RECT  63.853 10.344 64.716 10.416 ;
     RECT  63.853 10.416 64.692 10.44 ;
     RECT  63.853 10.44 64.716 10.512 ;
     RECT  63.853 10.512 64.692 10.536 ;
     RECT  63.853 10.536 64.716 10.608 ;
     RECT  63.853 10.608 64.692 10.632 ;
     RECT  63.853 10.632 64.716 10.704 ;
     RECT  63.853 10.704 64.692 10.728 ;
     RECT  63.853 10.728 64.716 10.8 ;
     RECT  63.853 10.8 64.692 10.824 ;
     RECT  63.853 10.824 64.716 10.896 ;
     RECT  63.853 10.896 64.692 10.92 ;
     RECT  63.853 10.92 64.716 10.992 ;
     RECT  63.853 10.992 64.692 11.016 ;
     RECT  63.853 11.016 64.716 11.088 ;
     RECT  63.853 11.088 64.692 11.112 ;
     RECT  63.853 11.112 64.716 11.184 ;
     RECT  63.853 11.184 64.692 11.208 ;
     RECT  63.853 11.208 64.716 11.28 ;
     RECT  63.853 11.28 64.692 11.304 ;
     RECT  63.853 11.304 64.716 11.376 ;
     RECT  63.853 11.376 64.692 11.4 ;
     RECT  63.853 11.4 64.716 11.472 ;
     RECT  63.853 11.472 64.692 11.496 ;
     RECT  63.853 11.496 64.716 11.568 ;
     RECT  63.853 11.568 64.692 11.592 ;
     RECT  63.853 11.592 64.716 11.664 ;
     RECT  63.853 11.664 64.692 11.688 ;
     RECT  63.853 11.688 64.716 11.76 ;
     RECT  63.853 11.76 64.692 11.784 ;
     RECT  63.853 11.784 64.716 11.856 ;
     RECT  63.853 11.856 64.692 11.88 ;
     RECT  63.853 11.88 64.716 11.952 ;
     RECT  63.853 11.952 64.692 11.976 ;
     RECT  63.853 11.976 64.716 12.048 ;
     RECT  63.853 12.048 64.692 12.072 ;
     RECT  63.853 12.072 64.716 12.144 ;
     RECT  63.853 12.144 64.692 12.168 ;
     RECT  63.853 12.168 64.716 12.24 ;
     RECT  63.853 12.24 64.692 12.264 ;
     RECT  63.853 12.264 64.716 12.336 ;
     RECT  63.853 12.336 64.692 12.36 ;
     RECT  63.853 12.36 64.716 12.432 ;
     RECT  63.853 12.432 64.692 12.456 ;
     RECT  63.853 12.456 64.716 12.528 ;
     RECT  63.853 12.528 64.692 12.552 ;
     RECT  63.853 12.552 64.716 12.624 ;
     RECT  63.853 12.624 64.692 12.648 ;
     RECT  63.853 12.648 64.716 12.72 ;
     RECT  63.853 12.72 64.692 12.744 ;
     RECT  63.853 12.744 64.716 12.816 ;
     RECT  63.853 12.816 64.692 12.84 ;
     RECT  63.853 12.84 64.716 12.912 ;
     RECT  63.853 12.912 64.692 12.936 ;
     RECT  63.853 19.92 64.692 19.944 ;
     RECT  63.853 19.944 64.716 20.016 ;
     RECT  63.853 20.016 64.692 20.04 ;
     RECT  63.853 20.04 64.716 20.112 ;
     RECT  63.853 20.112 64.692 20.136 ;
     RECT  63.853 20.136 64.716 20.208 ;
     RECT  63.853 20.208 64.692 20.232 ;
     RECT  63.853 20.232 64.716 20.304 ;
     RECT  63.853 20.304 64.692 20.328 ;
     RECT  63.853 20.328 64.716 20.4 ;
     RECT  63.853 20.4 64.692 20.424 ;
     RECT  63.853 20.424 64.716 20.496 ;
     RECT  63.853 20.496 64.692 20.52 ;
     RECT  63.853 20.52 64.716 20.592 ;
     RECT  63.853 20.592 64.692 20.616 ;
     RECT  63.853 20.616 64.716 20.688 ;
     RECT  63.853 20.688 64.692 20.712 ;
     RECT  63.853 20.712 64.716 20.784 ;
     RECT  63.853 20.784 64.692 20.808 ;
     RECT  63.853 20.808 64.716 20.88 ;
     RECT  63.853 20.88 64.692 20.904 ;
     RECT  63.853 20.904 64.716 20.976 ;
     RECT  63.853 20.976 64.692 21 ;
     RECT  63.853 21 64.716 21.072 ;
     RECT  63.853 21.072 64.692 21.096 ;
     RECT  63.853 21.096 64.716 21.168 ;
     RECT  63.853 21.168 64.692 21.192 ;
     RECT  63.853 21.192 64.716 21.264 ;
     RECT  63.853 21.264 64.692 21.288 ;
     RECT  63.853 21.288 64.716 21.36 ;
     RECT  63.853 21.36 64.692 21.384 ;
     RECT  63.853 21.384 64.716 21.456 ;
     RECT  63.853 21.456 64.692 21.48 ;
     RECT  63.853 21.48 64.716 21.552 ;
     RECT  63.853 21.552 64.692 21.576 ;
     RECT  63.853 21.576 64.716 21.648 ;
     RECT  63.853 21.648 64.692 21.672 ;
     RECT  63.853 21.672 64.716 21.744 ;
     RECT  63.853 21.744 64.692 21.768 ;
     RECT  63.853 21.768 64.716 21.84 ;
     RECT  63.853 21.84 64.692 21.864 ;
     RECT  63.853 21.864 64.716 21.936 ;
     RECT  63.853 21.936 64.692 21.96 ;
     RECT  63.853 21.96 64.716 22.032 ;
     RECT  63.853 22.032 64.692 22.056 ;
     RECT  63.853 22.056 64.716 22.128 ;
     RECT  63.853 22.128 64.692 22.152 ;
     RECT  63.853 22.152 64.716 22.224 ;
     RECT  63.853 22.224 64.692 22.248 ;
     RECT  63.853 22.248 64.716 22.32 ;
     RECT  63.853 22.32 64.692 22.344 ;
     RECT  63.853 22.344 64.716 22.416 ;
     RECT  63.853 22.416 64.692 22.44 ;
     RECT  63.853 22.44 64.716 22.512 ;
     RECT  63.853 22.512 64.692 22.536 ;
     RECT  63.853 22.536 64.716 22.608 ;
     RECT  63.853 22.608 64.692 22.632 ;
     RECT  63.853 22.632 64.716 22.704 ;
     RECT  63.853 22.704 64.692 22.728 ;
     RECT  63.853 22.728 64.716 22.8 ;
     RECT  63.853 22.8 64.692 22.824 ;
     RECT  63.853 22.824 64.716 22.896 ;
     RECT  63.853 22.896 64.692 22.92 ;
     RECT  63.853 22.92 64.716 22.992 ;
     RECT  63.853 22.992 64.692 23.016 ;
     RECT  63.853 23.016 64.716 23.088 ;
     RECT  63.853 23.088 64.692 23.112 ;
     RECT  63.853 23.112 64.716 23.184 ;
     RECT  63.853 23.184 64.692 23.208 ;
     RECT  63.853 23.208 64.716 23.28 ;
     RECT  63.853 23.28 64.692 23.304 ;
     RECT  63.853 23.304 64.716 23.376 ;
     RECT  63.853 23.376 64.692 23.4 ;
     RECT  63.853 23.4 64.716 23.472 ;
     RECT  63.853 23.472 64.692 23.496 ;
     RECT  63.853 23.496 64.716 23.568 ;
     RECT  63.853 23.568 64.692 23.592 ;
     RECT  63.853 23.592 64.716 23.664 ;
     RECT  63.853 23.664 64.692 23.688 ;
     RECT  63.853 23.688 64.716 23.76 ;
     RECT  63.853 23.76 64.692 23.784 ;
     RECT  63.853 23.784 64.716 23.856 ;
     RECT  63.853 23.856 64.692 23.88 ;
     RECT  63.853 23.88 64.716 23.952 ;
     RECT  63.853 23.952 64.692 23.976 ;
     RECT  63.853 23.976 64.716 24.048 ;
     RECT  63.853 24.048 64.692 24.072 ;
     RECT  63.853 24.072 64.716 24.144 ;
     RECT  63.853 24.144 64.692 24.168 ;
     RECT  63.853 24.168 64.716 24.24 ;
     RECT  63.853 24.24 64.692 24.264 ;
     RECT  63.853 24.264 64.716 24.336 ;
     RECT  63.853 24.336 64.692 24.36 ;
     RECT  63.853 24.36 64.716 24.432 ;
     RECT  63.853 24.432 64.692 24.456 ;
     RECT  63.853 24.456 64.716 24.528 ;
     RECT  63.853 24.528 64.692 24.552 ;
     RECT  63.853 24.552 64.716 24.624 ;
     RECT  63.853 24.624 64.692 24.648 ;
     RECT  63.853 24.648 64.716 24.72 ;
     RECT  63.853 24.72 64.692 24.744 ;
     RECT  63.853 24.744 64.716 24.816 ;
     RECT  63.853 24.816 64.692 24.84 ;
     RECT  63.853 24.84 64.716 24.912 ;
     RECT  63.853 24.912 64.692 24.936 ;
     RECT  63.853 24.936 64.716 25.008 ;
     RECT  63.853 25.008 64.692 25.032 ;
     RECT  63.853 25.032 64.716 25.104 ;
     RECT  63.853 25.104 64.692 25.128 ;
     RECT  63.853 25.128 64.716 25.2 ;
     RECT  63.853 25.2 64.692 25.224 ;
     RECT  63.853 25.224 64.716 25.296 ;
     RECT  63.853 25.296 64.692 25.32 ;
     RECT  63.853 25.32 64.716 25.392 ;
     RECT  63.853 25.392 64.692 25.416 ;
     RECT  63.853 25.416 64.716 25.488 ;
     RECT  63.853 25.488 64.692 25.512 ;
     RECT  63.853 25.512 64.716 25.584 ;
     RECT  63.853 25.584 64.692 25.608 ;
     RECT  63.853 25.608 64.716 25.68 ;
     RECT  63.853 25.68 64.692 25.704 ;
     RECT  63.853 25.704 64.716 25.776 ;
     RECT  63.853 25.776 64.692 25.8 ;
     RECT  63.853 25.8 64.716 25.872 ;
     RECT  63.853 25.872 64.692 25.896 ;
     RECT  63.853 25.896 64.716 25.968 ;
     RECT  63.853 25.968 64.692 25.992 ;
     RECT  64.716 8.448 64.757 8.496 ;
     RECT  64.716 8.52 64.757 8.592 ;
     RECT  64.716 8.616 64.757 8.688 ;
     RECT  64.716 8.712 64.757 8.784 ;
     RECT  64.716 8.808 64.757 8.88 ;
     RECT  64.716 8.904 64.757 8.976 ;
     RECT  64.716 9 64.757 9.072 ;
     RECT  64.716 9.096 64.757 9.168 ;
     RECT  64.716 9.192 64.757 9.24 ;
     RECT  64.716 24.96 64.757 24.984 ;
    LAYER M5 ;
     RECT  2.4 2.137 2.52 2.151 ;
     RECT  5.1 2.137 5.22 2.151 ;
     RECT  7.8 2.137 7.92 2.151 ;
     RECT  10.5 2.137 10.62 2.151 ;
     RECT  13.2 2.137 13.32 2.151 ;
     RECT  15.9 2.137 16.02 2.151 ;
     RECT  18.6 2.137 18.72 2.151 ;
     RECT  21.3 2.137 21.42 2.151 ;
     RECT  24 2.137 24.12 2.151 ;
     RECT  26.7 2.137 26.82 2.151 ;
     RECT  29.4 2.137 29.52 2.151 ;
     RECT  32.1 2.137 32.22 2.151 ;
     RECT  34.8 2.137 34.92 2.151 ;
     RECT  37.5 2.137 37.62 2.151 ;
     RECT  40.2 2.137 40.32 2.151 ;
     RECT  42.9 2.137 43.02 2.151 ;
     RECT  45.6 2.137 45.72 2.151 ;
     RECT  48.3 2.137 48.42 2.151 ;
     RECT  51 2.137 51.12 2.151 ;
     RECT  53.7 2.137 53.82 2.151 ;
     RECT  56.4 2.137 56.52 2.151 ;
     RECT  59.1 2.137 59.22 2.151 ;
     RECT  61.8 2.137 61.92 2.151 ;
     RECT  59.1 2.151 59.412 7.093 ;
     RECT  61.8 2.151 62.112 7.285 ;
     RECT  59.1 7.093 60.36 7.333 ;
     RECT  61.8 7.285 62.472 7.381 ;
     RECT  59.1 7.333 60.408 8.051 ;
     RECT  61.8 7.381 62.664 8.243 ;
     RECT  61.8 8.243 62.472 8.339 ;
     RECT  59.1 8.051 59.412 8.437 ;
     RECT  26.7 2.151 27.012 8.485 ;
     RECT  60.384 8.051 60.408 8.579 ;
     RECT  24 2.151 24.312 9.061 ;
     RECT  34.8 2.151 35.112 9.061 ;
     RECT  40.2 2.151 40.512 9.061 ;
     RECT  45.6 2.151 45.912 9.109 ;
     RECT  29.4 2.151 29.712 9.349 ;
     RECT  0.192 9.349 0.216 9.445 ;
     RECT  51 2.151 51.312 9.637 ;
     RECT  45.6 9.109 46.008 9.683 ;
     RECT  58.656 8.437 59.412 9.731 ;
     RECT  26.7 8.485 27.288 9.779 ;
     RECT  40.2 9.061 40.632 9.923 ;
     RECT  48.3 2.151 48.612 10.069 ;
     RECT  61.8 8.339 62.112 10.165 ;
     RECT  5.1 2.151 5.412 10.213 ;
     RECT  50.16 9.637 51.312 10.307 ;
     RECT  25.632 10.261 25.656 10.789 ;
     RECT  26.7 9.779 27.012 10.789 ;
     RECT  42.9 2.151 43.212 10.789 ;
     RECT  25.632 10.789 27.012 10.931 ;
     RECT  4.512 10.213 5.412 11.027 ;
     RECT  37.5 2.151 37.812 11.125 ;
     RECT  45.6 9.683 45.912 11.125 ;
     RECT  15.9 2.151 16.212 11.173 ;
     RECT  29.4 9.349 30.264 11.173 ;
     RECT  29.4 11.173 30.84 11.219 ;
     RECT  44.736 11.125 45.912 11.315 ;
     RECT  32.1 2.151 32.412 11.317 ;
     RECT  33.408 10.213 33.432 11.317 ;
     RECT  32.1 11.317 33.432 11.363 ;
     RECT  34.8 9.061 35.592 11.411 ;
     RECT  23.808 9.061 24.312 11.459 ;
     RECT  61.68 10.165 62.112 11.795 ;
     RECT  37.392 11.125 37.812 11.845 ;
     RECT  51 10.307 51.312 11.845 ;
     RECT  50.4 11.845 51.312 11.893 ;
     RECT  42.9 10.789 43.32 11.941 ;
     RECT  37.056 11.845 37.812 11.987 ;
     RECT  48.096 10.069 48.612 12.083 ;
     RECT  32.1 11.363 33.096 12.275 ;
     RECT  49.872 11.893 51.312 12.373 ;
     RECT  30.816 11.219 30.84 12.467 ;
     RECT  21.3 2.151 21.612 12.469 ;
     RECT  40.2 9.923 40.512 12.517 ;
     RECT  32.1 12.275 32.568 12.757 ;
     RECT  45.024 11.315 45.912 12.805 ;
     RECT  24 11.459 24.312 12.901 ;
     RECT  25.92 10.931 27.012 13.045 ;
     RECT  45.024 12.805 46.008 13.093 ;
     RECT  15.504 11.173 16.212 13.283 ;
     RECT  42.9 11.941 43.656 13.381 ;
     RECT  34.8 11.411 35.112 13.429 ;
     RECT  13.2 2.151 13.512 13.621 ;
     RECT  25.92 13.045 27.288 13.621 ;
     RECT  29.4 11.219 29.712 13.621 ;
     RECT  37.248 11.987 37.812 13.621 ;
     RECT  39.36 12.517 40.512 13.621 ;
     RECT  45.024 13.093 46.152 13.715 ;
     RECT  23.856 12.901 24.312 13.955 ;
     RECT  45.024 13.715 46.056 14.099 ;
     RECT  24 13.955 24.312 14.149 ;
     RECT  34.8 13.429 35.352 14.197 ;
     RECT  53.7 2.151 54.012 14.197 ;
     RECT  37.248 13.621 40.512 14.243 ;
     RECT  37.392 14.243 38.76 14.291 ;
     RECT  45.216 14.099 46.056 14.291 ;
     RECT  25.68 13.621 27.288 14.435 ;
     RECT  12.096 12.469 12.12 14.629 ;
     RECT  11.952 14.629 12.12 14.675 ;
     RECT  53.7 14.197 54.696 14.819 ;
     RECT  49.824 12.373 51.312 14.867 ;
     RECT  13.2 13.621 14.28 14.915 ;
     RECT  33.84 14.197 35.352 14.915 ;
     RECT  53.7 14.819 54.552 14.915 ;
     RECT  45.6 14.291 46.056 14.917 ;
     RECT  24 14.149 24.408 14.963 ;
     RECT  29.4 13.621 30.216 15.059 ;
     RECT  21.024 12.469 21.612 15.061 ;
     RECT  49.824 14.867 49.992 15.155 ;
     RECT  48.3 12.083 48.612 15.205 ;
     RECT  33.84 14.915 35.112 15.443 ;
     RECT  31.92 12.757 32.568 16.019 ;
     RECT  48.3 15.205 48.936 16.019 ;
     RECT  17.472 10.597 17.496 16.021 ;
     RECT  18.6 2.151 18.912 16.021 ;
     RECT  42.096 13.381 43.656 16.309 ;
     RECT  37.5 14.291 38.76 16.405 ;
     RECT  40.2 14.243 40.512 16.405 ;
     RECT  45.6 14.917 46.152 16.405 ;
     RECT  13.2 14.915 13.512 16.501 ;
     RECT  24 14.963 24.312 16.501 ;
     RECT  34.8 15.443 35.112 16.501 ;
     RECT  53.7 14.915 54.168 16.501 ;
     RECT  11.952 14.675 11.976 16.595 ;
     RECT  49.968 15.155 49.992 16.885 ;
     RECT  51 14.867 51.312 16.885 ;
     RECT  52.464 13.669 52.488 16.885 ;
     RECT  53.7 16.501 54.696 16.885 ;
     RECT  52.464 16.885 54.696 16.931 ;
     RECT  13.2 16.501 14.232 17.077 ;
     RECT  15.9 13.283 16.212 17.077 ;
     RECT  17.472 16.021 18.912 17.077 ;
     RECT  45.6 16.405 46.2 17.171 ;
     RECT  15.9 17.077 18.912 17.219 ;
     RECT  20.544 15.061 21.612 17.651 ;
     RECT  13.104 17.077 14.232 17.699 ;
     RECT  37.5 16.405 40.512 17.699 ;
     RECT  49.968 16.885 51.312 17.699 ;
     RECT  34.8 16.501 35.928 17.797 ;
     RECT  34.8 17.797 36.264 17.843 ;
     RECT  24 16.501 24.408 17.987 ;
     RECT  40.2 17.699 40.512 18.181 ;
     RECT  42 16.309 43.656 18.181 ;
     RECT  52.848 16.931 54.696 18.419 ;
     RECT  15.9 17.219 16.212 18.421 ;
     RECT  48.3 16.019 48.612 18.469 ;
     RECT  40.2 18.181 43.656 18.565 ;
     RECT  61.8 11.795 62.112 18.565 ;
     RECT  13.104 17.699 13.512 18.613 ;
     RECT  25.68 14.435 27.012 18.613 ;
     RECT  33.648 17.605 33.672 18.659 ;
     RECT  48.3 18.469 48.744 18.661 ;
     RECT  56.4 2.151 56.712 18.709 ;
     RECT  37.5 17.699 38.856 18.757 ;
     RECT  40.2 18.565 44.232 18.757 ;
     RECT  45.6 17.171 46.056 18.757 ;
     RECT  61.2 18.565 62.112 18.757 ;
     RECT  0.192 9.445 0.36 18.851 ;
     RECT  36.24 17.843 36.264 18.899 ;
     RECT  48.3 18.661 49.416 18.995 ;
     RECT  50.736 17.699 51.312 18.995 ;
     RECT  0.336 18.851 0.36 19.043 ;
     RECT  29.4 15.059 29.712 19.333 ;
     RECT  12.672 18.613 13.512 19.427 ;
     RECT  31.92 16.019 32.412 19.525 ;
     RECT  40.2 18.757 46.056 19.571 ;
     RECT  31.92 19.525 33.144 19.621 ;
     RECT  40.2 19.571 45.912 19.667 ;
     RECT  37.392 18.757 38.856 19.763 ;
     RECT  21.168 17.651 21.612 19.765 ;
     RECT  15.072 18.421 16.212 19.811 ;
     RECT  25.68 18.613 28.008 19.859 ;
     RECT  31.92 19.621 33.288 19.909 ;
     RECT  26.208 19.859 28.008 19.955 ;
     RECT  37.392 19.763 38.76 19.955 ;
     RECT  20.064 19.333 20.088 20.003 ;
     RECT  40.2 19.667 43.656 20.003 ;
     RECT  44.736 19.667 45.912 20.051 ;
     RECT  52.848 18.419 54.12 20.051 ;
     RECT  37.392 19.955 38.472 20.053 ;
     RECT  56.064 18.709 56.712 20.099 ;
     RECT  61.008 18.757 62.112 20.435 ;
     RECT  17.472 17.219 18.912 20.533 ;
     RECT  31.584 19.909 33.288 20.579 ;
     RECT  21.168 19.765 22.536 20.869 ;
     RECT  48.3 18.995 48.744 20.965 ;
     RECT  20.496 20.869 22.536 21.061 ;
     RECT  51 18.995 51.312 21.061 ;
     RECT  17.472 20.533 19.032 21.107 ;
     RECT  36.192 19.333 36.216 21.107 ;
     RECT  50.88 21.061 51.312 21.109 ;
     RECT  17.904 21.107 19.032 21.155 ;
     RECT  26.208 19.955 27.144 21.155 ;
     RECT  60.576 20.437 60.6 21.155 ;
     RECT  37.296 20.053 38.472 21.299 ;
     RECT  52.848 20.051 54.012 21.301 ;
     RECT  50.88 21.109 51.432 21.347 ;
     RECT  61.8 20.435 62.112 21.397 ;
     RECT  29.4 19.333 30.456 21.541 ;
     RECT  61.632 21.397 62.112 21.541 ;
     RECT  10.5 2.151 10.812 21.637 ;
     RECT  34.8 17.843 35.112 21.637 ;
     RECT  51 21.347 51.432 21.685 ;
     RECT  37.296 21.299 38.328 21.781 ;
     RECT  56.4 20.099 56.712 21.829 ;
     RECT  37.056 21.781 38.328 21.923 ;
     RECT  55.824 21.829 56.712 22.019 ;
     RECT  15.9 19.811 16.212 22.165 ;
     RECT  26.7 21.155 27.144 22.165 ;
     RECT  31.92 20.579 33.144 22.165 ;
     RECT  34.8 21.637 35.208 22.165 ;
     RECT  42 20.003 43.656 22.165 ;
     RECT  59.1 9.731 59.412 22.165 ;
     RECT  61.584 21.541 62.112 22.165 ;
     RECT  48.3 20.965 49.368 22.211 ;
     RECT  52.848 21.301 54.456 22.211 ;
     RECT  26.7 22.165 28.056 22.259 ;
     RECT  29.4 21.541 30.744 22.259 ;
     RECT  37.296 21.923 38.328 22.259 ;
     RECT  60.912 22.165 62.112 22.309 ;
     RECT  60.912 22.309 62.664 22.549 ;
     RECT  20.496 21.061 22.968 22.597 ;
     RECT  24 17.987 24.312 22.597 ;
     RECT  42 22.165 44.28 22.597 ;
     RECT  45.6 20.051 45.912 22.597 ;
     RECT  17.904 21.155 18.912 22.645 ;
     RECT  60.384 22.549 62.664 22.645 ;
     RECT  20.496 22.597 24.312 22.741 ;
     RECT  58.992 22.165 59.412 22.741 ;
     RECT  42 22.597 45.912 22.787 ;
     RECT  10.5 21.637 11.448 22.789 ;
     RECT  13.2 19.427 13.512 22.789 ;
     RECT  20.496 22.741 24.408 22.835 ;
     RECT  60.384 22.645 62.712 22.835 ;
     RECT  20.496 22.835 21.72 22.931 ;
     RECT  58.944 22.741 59.412 22.933 ;
     RECT  60.384 22.835 62.664 22.933 ;
     RECT  17.904 22.645 19.464 23.123 ;
     RECT  58.944 22.933 62.664 23.123 ;
     RECT  48.3 22.211 48.936 23.173 ;
     RECT  51 21.685 51.864 23.173 ;
     RECT  29.4 22.259 29.712 23.221 ;
     RECT  50.88 23.173 51.864 23.221 ;
     RECT  52.848 22.211 54.012 23.221 ;
     RECT  9.264 22.165 9.288 23.267 ;
     RECT  22.752 22.835 24.408 23.269 ;
     RECT  48.3 23.173 49.032 23.315 ;
     RECT  15.9 22.165 16.728 23.317 ;
     RECT  22.752 23.269 24.84 23.317 ;
     RECT  58.944 23.123 62.616 23.365 ;
     RECT  28.032 22.259 28.056 23.411 ;
     RECT  50.88 23.221 54.012 23.411 ;
     RECT  20.496 22.931 21.612 23.555 ;
     RECT  37.296 22.259 37.812 23.555 ;
     RECT  48.3 23.315 48.744 23.603 ;
     RECT  15.9 23.317 16.776 23.653 ;
     RECT  29.136 23.221 29.712 23.653 ;
     RECT  30.72 22.259 30.744 23.653 ;
     RECT  29.136 23.653 30.744 23.893 ;
     RECT  31.92 22.165 35.208 23.893 ;
     RECT  42 22.787 44.472 23.893 ;
     RECT  45.6 22.787 45.912 23.893 ;
     RECT  58.224 23.365 62.616 23.893 ;
     RECT  13.2 22.789 13.656 24.131 ;
     RECT  58.128 23.893 62.616 24.179 ;
     RECT  51 23.411 54.012 24.181 ;
     RECT  41.904 23.893 44.472 24.227 ;
     RECT  60.96 24.179 62.616 24.325 ;
     RECT  56.4 22.019 56.712 24.421 ;
     RECT  58.128 24.179 59.412 24.421 ;
     RECT  29.136 23.893 35.208 24.467 ;
     RECT  21.024 23.555 21.612 24.469 ;
     RECT  22.752 23.317 25.656 24.469 ;
     RECT  10.5 22.789 11.976 24.563 ;
     RECT  18.336 23.123 19.464 24.563 ;
     RECT  60.96 24.325 62.76 24.563 ;
     RECT  29.4 24.467 35.208 24.707 ;
     RECT  51 24.181 54.12 24.755 ;
     RECT  26.7 22.259 27.012 24.853 ;
     RECT  18.336 24.563 18.912 24.947 ;
     RECT  40.2 20.003 40.512 24.949 ;
     RECT  41.904 24.227 44.28 24.949 ;
     RECT  15.9 23.653 17.016 24.997 ;
     RECT  33.504 24.707 35.208 25.045 ;
     RECT  29.4 24.707 32.412 25.091 ;
     RECT  15.9 24.997 17.112 25.139 ;
     RECT  61.296 24.563 62.76 25.139 ;
     RECT  29.4 25.091 30.744 25.187 ;
     RECT  21.024 24.469 25.656 25.235 ;
     RECT  40.2 24.949 44.28 25.235 ;
     RECT  61.296 25.139 62.112 25.235 ;
     RECT  21.12 25.235 25.656 25.283 ;
     RECT  40.2 25.235 43.32 25.475 ;
     RECT  45.6 23.893 46.2 25.475 ;
     RECT  11.904 24.563 11.976 25.523 ;
     RECT  56.4 24.421 56.808 25.571 ;
     RECT  33.504 25.045 35.928 25.619 ;
     RECT  21.3 25.283 25.656 25.621 ;
     RECT  26.7 24.853 27.144 25.621 ;
     RECT  51 24.755 54.012 25.667 ;
     RECT  11.904 25.523 11.928 25.715 ;
     RECT  58.08 24.421 59.412 25.715 ;
     RECT  61.536 25.235 62.112 25.715 ;
     RECT  30.72 25.187 30.744 25.763 ;
     RECT  45.6 25.475 46.008 26.051 ;
     RECT  15.9 25.139 16.68 26.101 ;
     RECT  52.56 25.667 54.012 26.147 ;
     RECT  29.4 25.187 29.712 26.149 ;
     RECT  13.2 24.131 13.512 26.197 ;
     RECT  21.3 25.621 27.144 26.243 ;
     RECT  26.352 26.243 27.144 26.389 ;
     RECT  52.704 26.147 52.728 26.627 ;
     RECT  15.9 26.101 17.016 26.629 ;
     RECT  40.2 25.475 43.212 26.629 ;
     RECT  15.024 26.629 17.016 26.771 ;
     RECT  21.3 26.243 24.888 26.819 ;
     RECT  28.512 26.149 29.712 26.819 ;
     RECT  31.92 25.091 32.412 26.819 ;
     RECT  33.504 25.619 33.528 26.819 ;
     RECT  34.8 25.619 35.928 26.819 ;
     RECT  26.352 26.389 27.192 26.917 ;
     RECT  40.2 26.629 43.944 27.107 ;
     RECT  15.024 26.771 16.212 27.347 ;
     RECT  13.2 26.197 13.656 27.395 ;
     RECT  26.352 26.917 27.24 27.395 ;
     RECT  21.3 26.819 24.408 27.443 ;
     RECT  42.096 27.107 43.944 27.443 ;
     RECT  42.9 27.443 43.944 27.635 ;
     RECT  2.4 2.151 2.712 27.819 ;
     RECT  5.1 11.027 5.412 27.819 ;
     RECT  7.8 2.151 8.112 27.819 ;
     RECT  10.5 24.563 10.812 27.819 ;
     RECT  13.2 27.395 13.512 27.819 ;
     RECT  15.9 27.347 16.212 27.819 ;
     RECT  18.6 24.947 18.912 27.819 ;
     RECT  21.3 27.443 24.312 27.819 ;
     RECT  29.4 26.819 29.712 27.819 ;
     RECT  32.1 26.819 32.412 27.819 ;
     RECT  34.8 26.819 35.112 27.819 ;
     RECT  37.5 23.555 37.812 27.819 ;
     RECT  40.2 27.107 40.512 27.819 ;
     RECT  42.9 27.635 43.212 27.819 ;
     RECT  45.6 26.051 45.912 27.819 ;
     RECT  48.3 23.603 48.612 27.819 ;
     RECT  51 25.667 51.312 27.819 ;
     RECT  53.7 26.147 54.012 27.819 ;
     RECT  56.4 25.571 56.712 27.819 ;
     RECT  59.1 25.715 59.412 27.819 ;
     RECT  61.8 25.715 62.112 27.819 ;
     RECT  2.592 27.819 2.712 27.833 ;
     RECT  5.292 27.819 5.412 27.833 ;
     RECT  7.992 27.819 8.112 27.833 ;
     RECT  10.692 27.819 10.812 27.833 ;
     RECT  13.392 27.819 13.512 27.833 ;
     RECT  16.092 27.819 16.212 27.833 ;
     RECT  18.792 27.819 18.912 27.833 ;
     RECT  21.492 27.819 24.312 27.833 ;
     RECT  26.352 27.395 27.012 27.833 ;
     RECT  29.592 27.819 29.712 27.833 ;
     RECT  32.292 27.819 32.412 27.833 ;
     RECT  34.992 27.819 35.112 27.833 ;
     RECT  37.692 27.819 37.812 27.833 ;
     RECT  40.392 27.819 40.512 27.833 ;
     RECT  43.092 27.819 43.212 27.833 ;
     RECT  45.792 27.819 45.912 27.833 ;
     RECT  48.492 27.819 48.612 27.833 ;
     RECT  51.192 27.819 51.312 27.833 ;
     RECT  53.892 27.819 54.012 27.833 ;
     RECT  56.592 27.819 56.712 27.833 ;
     RECT  59.292 27.819 59.412 27.833 ;
     RECT  61.992 27.819 62.112 27.833 ;
     RECT  22.416 27.833 23.784 29.699 ;
     RECT  23.232 29.699 23.784 30.179 ;
     RECT  26.352 27.833 26.376 30.179 ;
     RECT  60.36 7.093 61.8 7.333 ;
     RECT  60.408 7.333 61.8 8.579 ;
     RECT  59.412 8.051 60.384 8.579 ;
     RECT  32.412 10.213 33.408 11.317 ;
     RECT  33.432 10.213 34.8 11.363 ;
     RECT  24.312 10.261 25.632 10.931 ;
     RECT  25.656 10.261 26.7 10.789 ;
     RECT  16.212 10.597 17.472 17.077 ;
     RECT  17.496 10.597 18.6 16.021 ;
     RECT  43.32 11.125 44.736 11.315 ;
     RECT  30.84 11.173 32.1 12.467 ;
     RECT  29.712 11.219 30.816 12.467 ;
     RECT  43.32 11.315 45.024 11.941 ;
     RECT  23.856 11.459 24 12.901 ;
     RECT  48.612 11.893 49.872 12.373 ;
     RECT  43.656 11.941 45.024 14.099 ;
     RECT  48.612 12.373 49.824 15.155 ;
     RECT  29.712 12.467 30.216 13.621 ;
     RECT  31.92 12.467 32.1 12.757 ;
     RECT  10.812 12.469 12.096 14.629 ;
     RECT  12.12 12.469 13.2 14.675 ;
     RECT  24.312 13.621 25.68 14.149 ;
     RECT  51.312 13.669 52.464 16.931 ;
     RECT  52.488 13.669 53.7 16.885 ;
     RECT  46.056 13.715 46.152 14.917 ;
     RECT  24.408 14.149 25.68 14.963 ;
     RECT  32.568 14.197 33.84 15.443 ;
     RECT  38.76 14.243 40.2 16.405 ;
     RECT  10.812 14.629 11.952 16.595 ;
     RECT  11.976 14.675 13.2 16.595 ;
     RECT  49.992 14.867 51 16.885 ;
     RECT  24.312 14.963 25.68 16.501 ;
     RECT  48.612 15.155 49.968 15.205 ;
     RECT  48.936 15.205 49.968 16.019 ;
     RECT  48.612 16.019 49.968 17.699 ;
     RECT  40.512 16.309 42 18.181 ;
     RECT  24.408 16.501 25.68 17.987 ;
     RECT  13.104 16.595 13.2 17.077 ;
     RECT  16.212 17.219 17.472 21.107 ;
     RECT  32.412 17.605 33.648 18.659 ;
     RECT  33.672 17.605 34.8 18.659 ;
     RECT  38.856 17.699 40.2 19.763 ;
     RECT  48.612 17.699 50.736 18.469 ;
     RECT  36.264 17.797 37.5 18.757 ;
     RECT  35.112 17.843 36.24 18.899 ;
     RECT  24.312 17.987 25.68 19.859 ;
     RECT  48.744 18.469 50.736 18.661 ;
     RECT  44.232 18.565 45.6 18.757 ;
     RECT  28.008 18.613 29.4 19.955 ;
     RECT  32.412 18.659 34.8 19.525 ;
     RECT  49.416 18.661 50.736 18.995 ;
     RECT  36.264 18.757 37.392 18.899 ;
     RECT  35.112 18.899 37.392 19.333 ;
     RECT  18.912 19.333 20.064 20.003 ;
     RECT  20.088 19.333 21.168 20.003 ;
     RECT  30.456 19.333 31.92 19.909 ;
     RECT  35.112 19.333 36.192 21.107 ;
     RECT  36.216 19.333 37.392 20.053 ;
     RECT  33.144 19.525 34.8 19.621 ;
     RECT  33.288 19.621 34.8 20.579 ;
     RECT  43.656 19.667 44.736 20.051 ;
     RECT  38.76 19.763 40.2 19.955 ;
     RECT  22.536 19.765 24 21.061 ;
     RECT  30.456 19.909 31.584 20.579 ;
     RECT  18.912 20.003 21.168 20.533 ;
     RECT  40.512 20.003 42 23.893 ;
     RECT  54.012 20.051 54.12 21.301 ;
     RECT  36.216 20.053 37.296 21.107 ;
     RECT  61.008 20.435 61.8 20.437 ;
     RECT  59.412 20.437 60.576 21.155 ;
     RECT  60.6 20.437 61.8 21.155 ;
     RECT  19.032 20.533 21.168 20.869 ;
     RECT  30.456 20.579 31.92 21.541 ;
     RECT  19.032 20.869 20.496 21.155 ;
     RECT  22.968 21.061 24 22.597 ;
     RECT  49.368 21.061 50.88 21.347 ;
     RECT  16.212 21.107 17.904 22.165 ;
     RECT  35.112 21.107 35.208 21.637 ;
     RECT  37.056 21.107 37.296 21.781 ;
     RECT  51.432 21.109 52.848 21.685 ;
     RECT  18.912 21.155 20.496 22.645 ;
     RECT  59.412 21.155 61.8 21.397 ;
     RECT  59.412 21.397 61.632 21.541 ;
     RECT  30.744 21.541 31.92 23.893 ;
     RECT  59.412 21.541 61.584 22.165 ;
     RECT  51.864 21.685 52.848 23.221 ;
     RECT  54.456 21.829 55.824 22.019 ;
     RECT  8.112 22.165 9.264 23.267 ;
     RECT  9.288 22.165 10.5 23.267 ;
     RECT  16.728 22.165 17.904 23.123 ;
     RECT  28.056 22.165 29.4 23.221 ;
     RECT  44.28 22.165 45.6 22.597 ;
     RECT  59.412 22.165 60.912 22.549 ;
     RECT  48.936 22.211 49.032 23.173 ;
     RECT  27.012 22.259 28.032 23.411 ;
     RECT  29.712 22.259 30.72 23.653 ;
     RECT  59.412 22.549 60.384 22.933 ;
     RECT  19.464 22.645 20.496 23.555 ;
     RECT  44.472 22.787 45.6 24.227 ;
     RECT  11.976 22.789 13.2 25.523 ;
     RECT  21.72 22.835 22.752 22.931 ;
     RECT  62.664 22.835 62.712 23.123 ;
     RECT  21.612 22.931 22.752 24.469 ;
     RECT  16.728 23.123 18.336 23.317 ;
     RECT  62.616 23.123 62.712 24.325 ;
     RECT  28.056 23.221 29.136 23.411 ;
     RECT  16.776 23.317 18.336 23.653 ;
     RECT  25.656 23.317 26.7 25.621 ;
     RECT  56.712 23.365 58.224 23.893 ;
     RECT  27.012 23.411 27.144 24.853 ;
     RECT  17.016 23.653 18.336 24.947 ;
     RECT  40.512 23.893 41.904 24.949 ;
     RECT  56.712 23.893 58.128 24.421 ;
     RECT  44.28 24.227 45.6 25.235 ;
     RECT  56.808 24.421 58.08 25.571 ;
     RECT  10.812 24.563 11.904 25.715 ;
     RECT  32.412 24.707 33.504 26.819 ;
     RECT  17.016 24.947 18.6 24.997 ;
     RECT  17.112 24.997 18.6 25.139 ;
     RECT  30.744 25.091 31.92 25.763 ;
     RECT  16.68 25.139 17.016 26.101 ;
     RECT  29.712 25.187 30.72 25.763 ;
     RECT  43.32 25.235 43.944 25.475 ;
     RECT  43.212 25.475 43.944 26.629 ;
     RECT  11.928 25.523 13.2 25.715 ;
     RECT  56.712 25.571 58.08 25.715 ;
     RECT  33.528 25.619 34.8 26.819 ;
     RECT  51.312 25.667 52.56 26.147 ;
     RECT  51.312 26.147 52.704 26.627 ;
     RECT  52.728 26.147 53.7 26.627 ;
     RECT  27.144 26.149 28.512 26.389 ;
     RECT  24.888 26.243 26.352 26.819 ;
     RECT  27.192 26.389 28.512 26.819 ;
     RECT  13.656 26.629 15.024 27.347 ;
     RECT  27.192 26.819 27.24 26.917 ;
  END
END qfd_landh0_128_EN_65x30
END LIBRARY
